# Generated by FakeRAM 2.0
VERSION 5.7 ;
BUSBITCHARS "[]" ;
PROPERTYDEFINITIONS
  MACRO width INTEGER ;
  MACRO depth INTEGER ;
  MACRO banks INTEGER ;
END PROPERTYDEFINITIONS
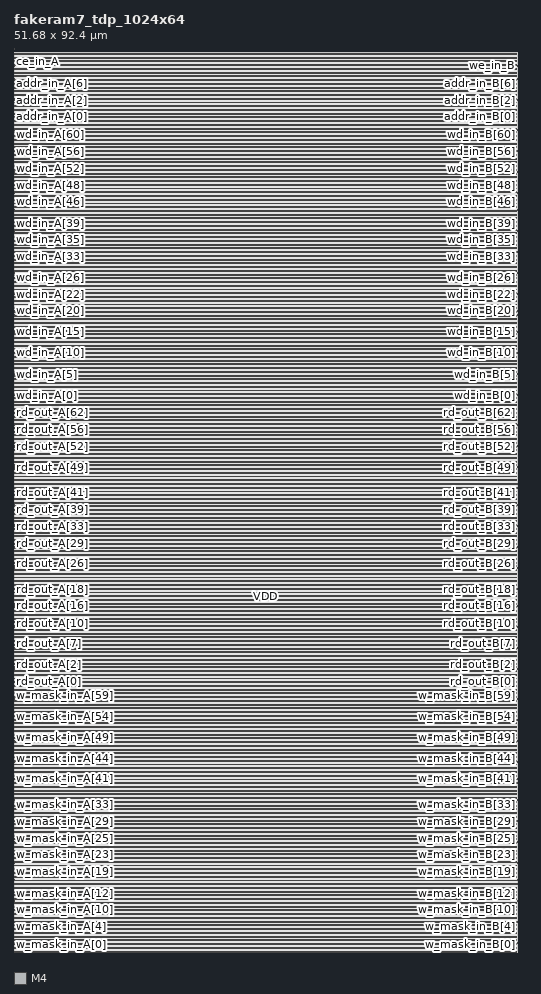
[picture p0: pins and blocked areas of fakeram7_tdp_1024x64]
MACRO fakeram7_tdp_1024x64
  PROPERTY width 64 ;
  PROPERTY depth 1024 ;
  PROPERTY banks 4 ;
  FOREIGN fakeram7_tdp_1024x64 0 0 ;
  SYMMETRY X Y ;
  SIZE 51.680 BY 92.400 ;
  CLASS BLOCK ;
  PIN w_mask_in_A[0]
    DIRECTION INPUT ;
    USE SIGNAL ;
    SHAPE ABUTMENT ;
    PORT
      LAYER M4 ;
      RECT 0.000 0.048 0.024 0.072 ;
    END
  END w_mask_in_A[0]
  PIN w_mask_in_B[0]
    DIRECTION INPUT ;
    USE SIGNAL ;
    SHAPE ABUTMENT ;
    PORT
      LAYER M4 ;
      RECT 51.656 0.048 51.680 0.072 ;
    END
  END w_mask_in_B[0]
  PIN w_mask_in_A[1]
    DIRECTION INPUT ;
    USE SIGNAL ;
    SHAPE ABUTMENT ;
    PORT
      LAYER M4 ;
      RECT 0.000 0.480 0.024 0.504 ;
    END
  END w_mask_in_A[1]
  PIN w_mask_in_B[1]
    DIRECTION INPUT ;
    USE SIGNAL ;
    SHAPE ABUTMENT ;
    PORT
      LAYER M4 ;
      RECT 51.656 0.480 51.680 0.504 ;
    END
  END w_mask_in_B[1]
  PIN w_mask_in_A[2]
    DIRECTION INPUT ;
    USE SIGNAL ;
    SHAPE ABUTMENT ;
    PORT
      LAYER M4 ;
      RECT 0.000 0.912 0.024 0.936 ;
    END
  END w_mask_in_A[2]
  PIN w_mask_in_B[2]
    DIRECTION INPUT ;
    USE SIGNAL ;
    SHAPE ABUTMENT ;
    PORT
      LAYER M4 ;
      RECT 51.656 0.912 51.680 0.936 ;
    END
  END w_mask_in_B[2]
  PIN w_mask_in_A[3]
    DIRECTION INPUT ;
    USE SIGNAL ;
    SHAPE ABUTMENT ;
    PORT
      LAYER M4 ;
      RECT 0.000 1.344 0.024 1.368 ;
    END
  END w_mask_in_A[3]
  PIN w_mask_in_B[3]
    DIRECTION INPUT ;
    USE SIGNAL ;
    SHAPE ABUTMENT ;
    PORT
      LAYER M4 ;
      RECT 51.656 1.344 51.680 1.368 ;
    END
  END w_mask_in_B[3]
  PIN w_mask_in_A[4]
    DIRECTION INPUT ;
    USE SIGNAL ;
    SHAPE ABUTMENT ;
    PORT
      LAYER M4 ;
      RECT 0.000 1.776 0.024 1.800 ;
    END
  END w_mask_in_A[4]
  PIN w_mask_in_B[4]
    DIRECTION INPUT ;
    USE SIGNAL ;
    SHAPE ABUTMENT ;
    PORT
      LAYER M4 ;
      RECT 51.656 1.776 51.680 1.800 ;
    END
  END w_mask_in_B[4]
  PIN w_mask_in_A[5]
    DIRECTION INPUT ;
    USE SIGNAL ;
    SHAPE ABUTMENT ;
    PORT
      LAYER M4 ;
      RECT 0.000 2.208 0.024 2.232 ;
    END
  END w_mask_in_A[5]
  PIN w_mask_in_B[5]
    DIRECTION INPUT ;
    USE SIGNAL ;
    SHAPE ABUTMENT ;
    PORT
      LAYER M4 ;
      RECT 51.656 2.208 51.680 2.232 ;
    END
  END w_mask_in_B[5]
  PIN w_mask_in_A[6]
    DIRECTION INPUT ;
    USE SIGNAL ;
    SHAPE ABUTMENT ;
    PORT
      LAYER M4 ;
      RECT 0.000 2.640 0.024 2.664 ;
    END
  END w_mask_in_A[6]
  PIN w_mask_in_B[6]
    DIRECTION INPUT ;
    USE SIGNAL ;
    SHAPE ABUTMENT ;
    PORT
      LAYER M4 ;
      RECT 51.656 2.640 51.680 2.664 ;
    END
  END w_mask_in_B[6]
  PIN w_mask_in_A[7]
    DIRECTION INPUT ;
    USE SIGNAL ;
    SHAPE ABUTMENT ;
    PORT
      LAYER M4 ;
      RECT 0.000 3.072 0.024 3.096 ;
    END
  END w_mask_in_A[7]
  PIN w_mask_in_B[7]
    DIRECTION INPUT ;
    USE SIGNAL ;
    SHAPE ABUTMENT ;
    PORT
      LAYER M4 ;
      RECT 51.656 3.072 51.680 3.096 ;
    END
  END w_mask_in_B[7]
  PIN w_mask_in_A[8]
    DIRECTION INPUT ;
    USE SIGNAL ;
    SHAPE ABUTMENT ;
    PORT
      LAYER M4 ;
      RECT 0.000 3.504 0.024 3.528 ;
    END
  END w_mask_in_A[8]
  PIN w_mask_in_B[8]
    DIRECTION INPUT ;
    USE SIGNAL ;
    SHAPE ABUTMENT ;
    PORT
      LAYER M4 ;
      RECT 51.656 3.504 51.680 3.528 ;
    END
  END w_mask_in_B[8]
  PIN w_mask_in_A[9]
    DIRECTION INPUT ;
    USE SIGNAL ;
    SHAPE ABUTMENT ;
    PORT
      LAYER M4 ;
      RECT 0.000 3.936 0.024 3.960 ;
    END
  END w_mask_in_A[9]
  PIN w_mask_in_B[9]
    DIRECTION INPUT ;
    USE SIGNAL ;
    SHAPE ABUTMENT ;
    PORT
      LAYER M4 ;
      RECT 51.656 3.936 51.680 3.960 ;
    END
  END w_mask_in_B[9]
  PIN w_mask_in_A[10]
    DIRECTION INPUT ;
    USE SIGNAL ;
    SHAPE ABUTMENT ;
    PORT
      LAYER M4 ;
      RECT 0.000 4.368 0.024 4.392 ;
    END
  END w_mask_in_A[10]
  PIN w_mask_in_B[10]
    DIRECTION INPUT ;
    USE SIGNAL ;
    SHAPE ABUTMENT ;
    PORT
      LAYER M4 ;
      RECT 51.656 4.368 51.680 4.392 ;
    END
  END w_mask_in_B[10]
  PIN w_mask_in_A[11]
    DIRECTION INPUT ;
    USE SIGNAL ;
    SHAPE ABUTMENT ;
    PORT
      LAYER M4 ;
      RECT 0.000 4.800 0.024 4.824 ;
    END
  END w_mask_in_A[11]
  PIN w_mask_in_B[11]
    DIRECTION INPUT ;
    USE SIGNAL ;
    SHAPE ABUTMENT ;
    PORT
      LAYER M4 ;
      RECT 51.656 4.800 51.680 4.824 ;
    END
  END w_mask_in_B[11]
  PIN w_mask_in_A[12]
    DIRECTION INPUT ;
    USE SIGNAL ;
    SHAPE ABUTMENT ;
    PORT
      LAYER M4 ;
      RECT 0.000 5.232 0.024 5.256 ;
    END
  END w_mask_in_A[12]
  PIN w_mask_in_B[12]
    DIRECTION INPUT ;
    USE SIGNAL ;
    SHAPE ABUTMENT ;
    PORT
      LAYER M4 ;
      RECT 51.656 5.232 51.680 5.256 ;
    END
  END w_mask_in_B[12]
  PIN w_mask_in_A[13]
    DIRECTION INPUT ;
    USE SIGNAL ;
    SHAPE ABUTMENT ;
    PORT
      LAYER M4 ;
      RECT 0.000 5.664 0.024 5.688 ;
    END
  END w_mask_in_A[13]
  PIN w_mask_in_B[13]
    DIRECTION INPUT ;
    USE SIGNAL ;
    SHAPE ABUTMENT ;
    PORT
      LAYER M4 ;
      RECT 51.656 5.664 51.680 5.688 ;
    END
  END w_mask_in_B[13]
  PIN w_mask_in_A[14]
    DIRECTION INPUT ;
    USE SIGNAL ;
    SHAPE ABUTMENT ;
    PORT
      LAYER M4 ;
      RECT 0.000 6.096 0.024 6.120 ;
    END
  END w_mask_in_A[14]
  PIN w_mask_in_B[14]
    DIRECTION INPUT ;
    USE SIGNAL ;
    SHAPE ABUTMENT ;
    PORT
      LAYER M4 ;
      RECT 51.656 6.096 51.680 6.120 ;
    END
  END w_mask_in_B[14]
  PIN w_mask_in_A[15]
    DIRECTION INPUT ;
    USE SIGNAL ;
    SHAPE ABUTMENT ;
    PORT
      LAYER M4 ;
      RECT 0.000 6.528 0.024 6.552 ;
    END
  END w_mask_in_A[15]
  PIN w_mask_in_B[15]
    DIRECTION INPUT ;
    USE SIGNAL ;
    SHAPE ABUTMENT ;
    PORT
      LAYER M4 ;
      RECT 51.656 6.528 51.680 6.552 ;
    END
  END w_mask_in_B[15]
  PIN w_mask_in_A[16]
    DIRECTION INPUT ;
    USE SIGNAL ;
    SHAPE ABUTMENT ;
    PORT
      LAYER M4 ;
      RECT 0.000 6.960 0.024 6.984 ;
    END
  END w_mask_in_A[16]
  PIN w_mask_in_B[16]
    DIRECTION INPUT ;
    USE SIGNAL ;
    SHAPE ABUTMENT ;
    PORT
      LAYER M4 ;
      RECT 51.656 6.960 51.680 6.984 ;
    END
  END w_mask_in_B[16]
  PIN w_mask_in_A[17]
    DIRECTION INPUT ;
    USE SIGNAL ;
    SHAPE ABUTMENT ;
    PORT
      LAYER M4 ;
      RECT 0.000 7.392 0.024 7.416 ;
    END
  END w_mask_in_A[17]
  PIN w_mask_in_B[17]
    DIRECTION INPUT ;
    USE SIGNAL ;
    SHAPE ABUTMENT ;
    PORT
      LAYER M4 ;
      RECT 51.656 7.392 51.680 7.416 ;
    END
  END w_mask_in_B[17]
  PIN w_mask_in_A[18]
    DIRECTION INPUT ;
    USE SIGNAL ;
    SHAPE ABUTMENT ;
    PORT
      LAYER M4 ;
      RECT 0.000 7.824 0.024 7.848 ;
    END
  END w_mask_in_A[18]
  PIN w_mask_in_B[18]
    DIRECTION INPUT ;
    USE SIGNAL ;
    SHAPE ABUTMENT ;
    PORT
      LAYER M4 ;
      RECT 51.656 7.824 51.680 7.848 ;
    END
  END w_mask_in_B[18]
  PIN w_mask_in_A[19]
    DIRECTION INPUT ;
    USE SIGNAL ;
    SHAPE ABUTMENT ;
    PORT
      LAYER M4 ;
      RECT 0.000 8.256 0.024 8.280 ;
    END
  END w_mask_in_A[19]
  PIN w_mask_in_B[19]
    DIRECTION INPUT ;
    USE SIGNAL ;
    SHAPE ABUTMENT ;
    PORT
      LAYER M4 ;
      RECT 51.656 8.256 51.680 8.280 ;
    END
  END w_mask_in_B[19]
  PIN w_mask_in_A[20]
    DIRECTION INPUT ;
    USE SIGNAL ;
    SHAPE ABUTMENT ;
    PORT
      LAYER M4 ;
      RECT 0.000 8.688 0.024 8.712 ;
    END
  END w_mask_in_A[20]
  PIN w_mask_in_B[20]
    DIRECTION INPUT ;
    USE SIGNAL ;
    SHAPE ABUTMENT ;
    PORT
      LAYER M4 ;
      RECT 51.656 8.688 51.680 8.712 ;
    END
  END w_mask_in_B[20]
  PIN w_mask_in_A[21]
    DIRECTION INPUT ;
    USE SIGNAL ;
    SHAPE ABUTMENT ;
    PORT
      LAYER M4 ;
      RECT 0.000 9.120 0.024 9.144 ;
    END
  END w_mask_in_A[21]
  PIN w_mask_in_B[21]
    DIRECTION INPUT ;
    USE SIGNAL ;
    SHAPE ABUTMENT ;
    PORT
      LAYER M4 ;
      RECT 51.656 9.120 51.680 9.144 ;
    END
  END w_mask_in_B[21]
  PIN w_mask_in_A[22]
    DIRECTION INPUT ;
    USE SIGNAL ;
    SHAPE ABUTMENT ;
    PORT
      LAYER M4 ;
      RECT 0.000 9.552 0.024 9.576 ;
    END
  END w_mask_in_A[22]
  PIN w_mask_in_B[22]
    DIRECTION INPUT ;
    USE SIGNAL ;
    SHAPE ABUTMENT ;
    PORT
      LAYER M4 ;
      RECT 51.656 9.552 51.680 9.576 ;
    END
  END w_mask_in_B[22]
  PIN w_mask_in_A[23]
    DIRECTION INPUT ;
    USE SIGNAL ;
    SHAPE ABUTMENT ;
    PORT
      LAYER M4 ;
      RECT 0.000 9.984 0.024 10.008 ;
    END
  END w_mask_in_A[23]
  PIN w_mask_in_B[23]
    DIRECTION INPUT ;
    USE SIGNAL ;
    SHAPE ABUTMENT ;
    PORT
      LAYER M4 ;
      RECT 51.656 9.984 51.680 10.008 ;
    END
  END w_mask_in_B[23]
  PIN w_mask_in_A[24]
    DIRECTION INPUT ;
    USE SIGNAL ;
    SHAPE ABUTMENT ;
    PORT
      LAYER M4 ;
      RECT 0.000 10.416 0.024 10.440 ;
    END
  END w_mask_in_A[24]
  PIN w_mask_in_B[24]
    DIRECTION INPUT ;
    USE SIGNAL ;
    SHAPE ABUTMENT ;
    PORT
      LAYER M4 ;
      RECT 51.656 10.416 51.680 10.440 ;
    END
  END w_mask_in_B[24]
  PIN w_mask_in_A[25]
    DIRECTION INPUT ;
    USE SIGNAL ;
    SHAPE ABUTMENT ;
    PORT
      LAYER M4 ;
      RECT 0.000 10.848 0.024 10.872 ;
    END
  END w_mask_in_A[25]
  PIN w_mask_in_B[25]
    DIRECTION INPUT ;
    USE SIGNAL ;
    SHAPE ABUTMENT ;
    PORT
      LAYER M4 ;
      RECT 51.656 10.848 51.680 10.872 ;
    END
  END w_mask_in_B[25]
  PIN w_mask_in_A[26]
    DIRECTION INPUT ;
    USE SIGNAL ;
    SHAPE ABUTMENT ;
    PORT
      LAYER M4 ;
      RECT 0.000 11.280 0.024 11.304 ;
    END
  END w_mask_in_A[26]
  PIN w_mask_in_B[26]
    DIRECTION INPUT ;
    USE SIGNAL ;
    SHAPE ABUTMENT ;
    PORT
      LAYER M4 ;
      RECT 51.656 11.280 51.680 11.304 ;
    END
  END w_mask_in_B[26]
  PIN w_mask_in_A[27]
    DIRECTION INPUT ;
    USE SIGNAL ;
    SHAPE ABUTMENT ;
    PORT
      LAYER M4 ;
      RECT 0.000 11.712 0.024 11.736 ;
    END
  END w_mask_in_A[27]
  PIN w_mask_in_B[27]
    DIRECTION INPUT ;
    USE SIGNAL ;
    SHAPE ABUTMENT ;
    PORT
      LAYER M4 ;
      RECT 51.656 11.712 51.680 11.736 ;
    END
  END w_mask_in_B[27]
  PIN w_mask_in_A[28]
    DIRECTION INPUT ;
    USE SIGNAL ;
    SHAPE ABUTMENT ;
    PORT
      LAYER M4 ;
      RECT 0.000 12.144 0.024 12.168 ;
    END
  END w_mask_in_A[28]
  PIN w_mask_in_B[28]
    DIRECTION INPUT ;
    USE SIGNAL ;
    SHAPE ABUTMENT ;
    PORT
      LAYER M4 ;
      RECT 51.656 12.144 51.680 12.168 ;
    END
  END w_mask_in_B[28]
  PIN w_mask_in_A[29]
    DIRECTION INPUT ;
    USE SIGNAL ;
    SHAPE ABUTMENT ;
    PORT
      LAYER M4 ;
      RECT 0.000 12.576 0.024 12.600 ;
    END
  END w_mask_in_A[29]
  PIN w_mask_in_B[29]
    DIRECTION INPUT ;
    USE SIGNAL ;
    SHAPE ABUTMENT ;
    PORT
      LAYER M4 ;
      RECT 51.656 12.576 51.680 12.600 ;
    END
  END w_mask_in_B[29]
  PIN w_mask_in_A[30]
    DIRECTION INPUT ;
    USE SIGNAL ;
    SHAPE ABUTMENT ;
    PORT
      LAYER M4 ;
      RECT 0.000 13.008 0.024 13.032 ;
    END
  END w_mask_in_A[30]
  PIN w_mask_in_B[30]
    DIRECTION INPUT ;
    USE SIGNAL ;
    SHAPE ABUTMENT ;
    PORT
      LAYER M4 ;
      RECT 51.656 13.008 51.680 13.032 ;
    END
  END w_mask_in_B[30]
  PIN w_mask_in_A[31]
    DIRECTION INPUT ;
    USE SIGNAL ;
    SHAPE ABUTMENT ;
    PORT
      LAYER M4 ;
      RECT 0.000 13.440 0.024 13.464 ;
    END
  END w_mask_in_A[31]
  PIN w_mask_in_B[31]
    DIRECTION INPUT ;
    USE SIGNAL ;
    SHAPE ABUTMENT ;
    PORT
      LAYER M4 ;
      RECT 51.656 13.440 51.680 13.464 ;
    END
  END w_mask_in_B[31]
  PIN w_mask_in_A[32]
    DIRECTION INPUT ;
    USE SIGNAL ;
    SHAPE ABUTMENT ;
    PORT
      LAYER M4 ;
      RECT 0.000 13.872 0.024 13.896 ;
    END
  END w_mask_in_A[32]
  PIN w_mask_in_B[32]
    DIRECTION INPUT ;
    USE SIGNAL ;
    SHAPE ABUTMENT ;
    PORT
      LAYER M4 ;
      RECT 51.656 13.872 51.680 13.896 ;
    END
  END w_mask_in_B[32]
  PIN w_mask_in_A[33]
    DIRECTION INPUT ;
    USE SIGNAL ;
    SHAPE ABUTMENT ;
    PORT
      LAYER M4 ;
      RECT 0.000 14.304 0.024 14.328 ;
    END
  END w_mask_in_A[33]
  PIN w_mask_in_B[33]
    DIRECTION INPUT ;
    USE SIGNAL ;
    SHAPE ABUTMENT ;
    PORT
      LAYER M4 ;
      RECT 51.656 14.304 51.680 14.328 ;
    END
  END w_mask_in_B[33]
  PIN w_mask_in_A[34]
    DIRECTION INPUT ;
    USE SIGNAL ;
    SHAPE ABUTMENT ;
    PORT
      LAYER M4 ;
      RECT 0.000 14.736 0.024 14.760 ;
    END
  END w_mask_in_A[34]
  PIN w_mask_in_B[34]
    DIRECTION INPUT ;
    USE SIGNAL ;
    SHAPE ABUTMENT ;
    PORT
      LAYER M4 ;
      RECT 51.656 14.736 51.680 14.760 ;
    END
  END w_mask_in_B[34]
  PIN w_mask_in_A[35]
    DIRECTION INPUT ;
    USE SIGNAL ;
    SHAPE ABUTMENT ;
    PORT
      LAYER M4 ;
      RECT 0.000 15.168 0.024 15.192 ;
    END
  END w_mask_in_A[35]
  PIN w_mask_in_B[35]
    DIRECTION INPUT ;
    USE SIGNAL ;
    SHAPE ABUTMENT ;
    PORT
      LAYER M4 ;
      RECT 51.656 15.168 51.680 15.192 ;
    END
  END w_mask_in_B[35]
  PIN w_mask_in_A[36]
    DIRECTION INPUT ;
    USE SIGNAL ;
    SHAPE ABUTMENT ;
    PORT
      LAYER M4 ;
      RECT 0.000 15.600 0.024 15.624 ;
    END
  END w_mask_in_A[36]
  PIN w_mask_in_B[36]
    DIRECTION INPUT ;
    USE SIGNAL ;
    SHAPE ABUTMENT ;
    PORT
      LAYER M4 ;
      RECT 51.656 15.600 51.680 15.624 ;
    END
  END w_mask_in_B[36]
  PIN w_mask_in_A[37]
    DIRECTION INPUT ;
    USE SIGNAL ;
    SHAPE ABUTMENT ;
    PORT
      LAYER M4 ;
      RECT 0.000 16.032 0.024 16.056 ;
    END
  END w_mask_in_A[37]
  PIN w_mask_in_B[37]
    DIRECTION INPUT ;
    USE SIGNAL ;
    SHAPE ABUTMENT ;
    PORT
      LAYER M4 ;
      RECT 51.656 16.032 51.680 16.056 ;
    END
  END w_mask_in_B[37]
  PIN w_mask_in_A[38]
    DIRECTION INPUT ;
    USE SIGNAL ;
    SHAPE ABUTMENT ;
    PORT
      LAYER M4 ;
      RECT 0.000 16.464 0.024 16.488 ;
    END
  END w_mask_in_A[38]
  PIN w_mask_in_B[38]
    DIRECTION INPUT ;
    USE SIGNAL ;
    SHAPE ABUTMENT ;
    PORT
      LAYER M4 ;
      RECT 51.656 16.464 51.680 16.488 ;
    END
  END w_mask_in_B[38]
  PIN w_mask_in_A[39]
    DIRECTION INPUT ;
    USE SIGNAL ;
    SHAPE ABUTMENT ;
    PORT
      LAYER M4 ;
      RECT 0.000 16.896 0.024 16.920 ;
    END
  END w_mask_in_A[39]
  PIN w_mask_in_B[39]
    DIRECTION INPUT ;
    USE SIGNAL ;
    SHAPE ABUTMENT ;
    PORT
      LAYER M4 ;
      RECT 51.656 16.896 51.680 16.920 ;
    END
  END w_mask_in_B[39]
  PIN w_mask_in_A[40]
    DIRECTION INPUT ;
    USE SIGNAL ;
    SHAPE ABUTMENT ;
    PORT
      LAYER M4 ;
      RECT 0.000 17.328 0.024 17.352 ;
    END
  END w_mask_in_A[40]
  PIN w_mask_in_B[40]
    DIRECTION INPUT ;
    USE SIGNAL ;
    SHAPE ABUTMENT ;
    PORT
      LAYER M4 ;
      RECT 51.656 17.328 51.680 17.352 ;
    END
  END w_mask_in_B[40]
  PIN w_mask_in_A[41]
    DIRECTION INPUT ;
    USE SIGNAL ;
    SHAPE ABUTMENT ;
    PORT
      LAYER M4 ;
      RECT 0.000 17.760 0.024 17.784 ;
    END
  END w_mask_in_A[41]
  PIN w_mask_in_B[41]
    DIRECTION INPUT ;
    USE SIGNAL ;
    SHAPE ABUTMENT ;
    PORT
      LAYER M4 ;
      RECT 51.656 17.760 51.680 17.784 ;
    END
  END w_mask_in_B[41]
  PIN w_mask_in_A[42]
    DIRECTION INPUT ;
    USE SIGNAL ;
    SHAPE ABUTMENT ;
    PORT
      LAYER M4 ;
      RECT 0.000 18.192 0.024 18.216 ;
    END
  END w_mask_in_A[42]
  PIN w_mask_in_B[42]
    DIRECTION INPUT ;
    USE SIGNAL ;
    SHAPE ABUTMENT ;
    PORT
      LAYER M4 ;
      RECT 51.656 18.192 51.680 18.216 ;
    END
  END w_mask_in_B[42]
  PIN w_mask_in_A[43]
    DIRECTION INPUT ;
    USE SIGNAL ;
    SHAPE ABUTMENT ;
    PORT
      LAYER M4 ;
      RECT 0.000 18.624 0.024 18.648 ;
    END
  END w_mask_in_A[43]
  PIN w_mask_in_B[43]
    DIRECTION INPUT ;
    USE SIGNAL ;
    SHAPE ABUTMENT ;
    PORT
      LAYER M4 ;
      RECT 51.656 18.624 51.680 18.648 ;
    END
  END w_mask_in_B[43]
  PIN w_mask_in_A[44]
    DIRECTION INPUT ;
    USE SIGNAL ;
    SHAPE ABUTMENT ;
    PORT
      LAYER M4 ;
      RECT 0.000 19.056 0.024 19.080 ;
    END
  END w_mask_in_A[44]
  PIN w_mask_in_B[44]
    DIRECTION INPUT ;
    USE SIGNAL ;
    SHAPE ABUTMENT ;
    PORT
      LAYER M4 ;
      RECT 51.656 19.056 51.680 19.080 ;
    END
  END w_mask_in_B[44]
  PIN w_mask_in_A[45]
    DIRECTION INPUT ;
    USE SIGNAL ;
    SHAPE ABUTMENT ;
    PORT
      LAYER M4 ;
      RECT 0.000 19.488 0.024 19.512 ;
    END
  END w_mask_in_A[45]
  PIN w_mask_in_B[45]
    DIRECTION INPUT ;
    USE SIGNAL ;
    SHAPE ABUTMENT ;
    PORT
      LAYER M4 ;
      RECT 51.656 19.488 51.680 19.512 ;
    END
  END w_mask_in_B[45]
  PIN w_mask_in_A[46]
    DIRECTION INPUT ;
    USE SIGNAL ;
    SHAPE ABUTMENT ;
    PORT
      LAYER M4 ;
      RECT 0.000 19.920 0.024 19.944 ;
    END
  END w_mask_in_A[46]
  PIN w_mask_in_B[46]
    DIRECTION INPUT ;
    USE SIGNAL ;
    SHAPE ABUTMENT ;
    PORT
      LAYER M4 ;
      RECT 51.656 19.920 51.680 19.944 ;
    END
  END w_mask_in_B[46]
  PIN w_mask_in_A[47]
    DIRECTION INPUT ;
    USE SIGNAL ;
    SHAPE ABUTMENT ;
    PORT
      LAYER M4 ;
      RECT 0.000 20.352 0.024 20.376 ;
    END
  END w_mask_in_A[47]
  PIN w_mask_in_B[47]
    DIRECTION INPUT ;
    USE SIGNAL ;
    SHAPE ABUTMENT ;
    PORT
      LAYER M4 ;
      RECT 51.656 20.352 51.680 20.376 ;
    END
  END w_mask_in_B[47]
  PIN w_mask_in_A[48]
    DIRECTION INPUT ;
    USE SIGNAL ;
    SHAPE ABUTMENT ;
    PORT
      LAYER M4 ;
      RECT 0.000 20.784 0.024 20.808 ;
    END
  END w_mask_in_A[48]
  PIN w_mask_in_B[48]
    DIRECTION INPUT ;
    USE SIGNAL ;
    SHAPE ABUTMENT ;
    PORT
      LAYER M4 ;
      RECT 51.656 20.784 51.680 20.808 ;
    END
  END w_mask_in_B[48]
  PIN w_mask_in_A[49]
    DIRECTION INPUT ;
    USE SIGNAL ;
    SHAPE ABUTMENT ;
    PORT
      LAYER M4 ;
      RECT 0.000 21.216 0.024 21.240 ;
    END
  END w_mask_in_A[49]
  PIN w_mask_in_B[49]
    DIRECTION INPUT ;
    USE SIGNAL ;
    SHAPE ABUTMENT ;
    PORT
      LAYER M4 ;
      RECT 51.656 21.216 51.680 21.240 ;
    END
  END w_mask_in_B[49]
  PIN w_mask_in_A[50]
    DIRECTION INPUT ;
    USE SIGNAL ;
    SHAPE ABUTMENT ;
    PORT
      LAYER M4 ;
      RECT 0.000 21.648 0.024 21.672 ;
    END
  END w_mask_in_A[50]
  PIN w_mask_in_B[50]
    DIRECTION INPUT ;
    USE SIGNAL ;
    SHAPE ABUTMENT ;
    PORT
      LAYER M4 ;
      RECT 51.656 21.648 51.680 21.672 ;
    END
  END w_mask_in_B[50]
  PIN w_mask_in_A[51]
    DIRECTION INPUT ;
    USE SIGNAL ;
    SHAPE ABUTMENT ;
    PORT
      LAYER M4 ;
      RECT 0.000 22.080 0.024 22.104 ;
    END
  END w_mask_in_A[51]
  PIN w_mask_in_B[51]
    DIRECTION INPUT ;
    USE SIGNAL ;
    SHAPE ABUTMENT ;
    PORT
      LAYER M4 ;
      RECT 51.656 22.080 51.680 22.104 ;
    END
  END w_mask_in_B[51]
  PIN w_mask_in_A[52]
    DIRECTION INPUT ;
    USE SIGNAL ;
    SHAPE ABUTMENT ;
    PORT
      LAYER M4 ;
      RECT 0.000 22.512 0.024 22.536 ;
    END
  END w_mask_in_A[52]
  PIN w_mask_in_B[52]
    DIRECTION INPUT ;
    USE SIGNAL ;
    SHAPE ABUTMENT ;
    PORT
      LAYER M4 ;
      RECT 51.656 22.512 51.680 22.536 ;
    END
  END w_mask_in_B[52]
  PIN w_mask_in_A[53]
    DIRECTION INPUT ;
    USE SIGNAL ;
    SHAPE ABUTMENT ;
    PORT
      LAYER M4 ;
      RECT 0.000 22.944 0.024 22.968 ;
    END
  END w_mask_in_A[53]
  PIN w_mask_in_B[53]
    DIRECTION INPUT ;
    USE SIGNAL ;
    SHAPE ABUTMENT ;
    PORT
      LAYER M4 ;
      RECT 51.656 22.944 51.680 22.968 ;
    END
  END w_mask_in_B[53]
  PIN w_mask_in_A[54]
    DIRECTION INPUT ;
    USE SIGNAL ;
    SHAPE ABUTMENT ;
    PORT
      LAYER M4 ;
      RECT 0.000 23.376 0.024 23.400 ;
    END
  END w_mask_in_A[54]
  PIN w_mask_in_B[54]
    DIRECTION INPUT ;
    USE SIGNAL ;
    SHAPE ABUTMENT ;
    PORT
      LAYER M4 ;
      RECT 51.656 23.376 51.680 23.400 ;
    END
  END w_mask_in_B[54]
  PIN w_mask_in_A[55]
    DIRECTION INPUT ;
    USE SIGNAL ;
    SHAPE ABUTMENT ;
    PORT
      LAYER M4 ;
      RECT 0.000 23.808 0.024 23.832 ;
    END
  END w_mask_in_A[55]
  PIN w_mask_in_B[55]
    DIRECTION INPUT ;
    USE SIGNAL ;
    SHAPE ABUTMENT ;
    PORT
      LAYER M4 ;
      RECT 51.656 23.808 51.680 23.832 ;
    END
  END w_mask_in_B[55]
  PIN w_mask_in_A[56]
    DIRECTION INPUT ;
    USE SIGNAL ;
    SHAPE ABUTMENT ;
    PORT
      LAYER M4 ;
      RECT 0.000 24.240 0.024 24.264 ;
    END
  END w_mask_in_A[56]
  PIN w_mask_in_B[56]
    DIRECTION INPUT ;
    USE SIGNAL ;
    SHAPE ABUTMENT ;
    PORT
      LAYER M4 ;
      RECT 51.656 24.240 51.680 24.264 ;
    END
  END w_mask_in_B[56]
  PIN w_mask_in_A[57]
    DIRECTION INPUT ;
    USE SIGNAL ;
    SHAPE ABUTMENT ;
    PORT
      LAYER M4 ;
      RECT 0.000 24.672 0.024 24.696 ;
    END
  END w_mask_in_A[57]
  PIN w_mask_in_B[57]
    DIRECTION INPUT ;
    USE SIGNAL ;
    SHAPE ABUTMENT ;
    PORT
      LAYER M4 ;
      RECT 51.656 24.672 51.680 24.696 ;
    END
  END w_mask_in_B[57]
  PIN w_mask_in_A[58]
    DIRECTION INPUT ;
    USE SIGNAL ;
    SHAPE ABUTMENT ;
    PORT
      LAYER M4 ;
      RECT 0.000 25.104 0.024 25.128 ;
    END
  END w_mask_in_A[58]
  PIN w_mask_in_B[58]
    DIRECTION INPUT ;
    USE SIGNAL ;
    SHAPE ABUTMENT ;
    PORT
      LAYER M4 ;
      RECT 51.656 25.104 51.680 25.128 ;
    END
  END w_mask_in_B[58]
  PIN w_mask_in_A[59]
    DIRECTION INPUT ;
    USE SIGNAL ;
    SHAPE ABUTMENT ;
    PORT
      LAYER M4 ;
      RECT 0.000 25.536 0.024 25.560 ;
    END
  END w_mask_in_A[59]
  PIN w_mask_in_B[59]
    DIRECTION INPUT ;
    USE SIGNAL ;
    SHAPE ABUTMENT ;
    PORT
      LAYER M4 ;
      RECT 51.656 25.536 51.680 25.560 ;
    END
  END w_mask_in_B[59]
  PIN w_mask_in_A[60]
    DIRECTION INPUT ;
    USE SIGNAL ;
    SHAPE ABUTMENT ;
    PORT
      LAYER M4 ;
      RECT 0.000 25.968 0.024 25.992 ;
    END
  END w_mask_in_A[60]
  PIN w_mask_in_B[60]
    DIRECTION INPUT ;
    USE SIGNAL ;
    SHAPE ABUTMENT ;
    PORT
      LAYER M4 ;
      RECT 51.656 25.968 51.680 25.992 ;
    END
  END w_mask_in_B[60]
  PIN w_mask_in_A[61]
    DIRECTION INPUT ;
    USE SIGNAL ;
    SHAPE ABUTMENT ;
    PORT
      LAYER M4 ;
      RECT 0.000 26.400 0.024 26.424 ;
    END
  END w_mask_in_A[61]
  PIN w_mask_in_B[61]
    DIRECTION INPUT ;
    USE SIGNAL ;
    SHAPE ABUTMENT ;
    PORT
      LAYER M4 ;
      RECT 51.656 26.400 51.680 26.424 ;
    END
  END w_mask_in_B[61]
  PIN w_mask_in_A[62]
    DIRECTION INPUT ;
    USE SIGNAL ;
    SHAPE ABUTMENT ;
    PORT
      LAYER M4 ;
      RECT 0.000 26.832 0.024 26.856 ;
    END
  END w_mask_in_A[62]
  PIN w_mask_in_B[62]
    DIRECTION INPUT ;
    USE SIGNAL ;
    SHAPE ABUTMENT ;
    PORT
      LAYER M4 ;
      RECT 51.656 26.832 51.680 26.856 ;
    END
  END w_mask_in_B[62]
  PIN w_mask_in_A[63]
    DIRECTION INPUT ;
    USE SIGNAL ;
    SHAPE ABUTMENT ;
    PORT
      LAYER M4 ;
      RECT 0.000 27.264 0.024 27.288 ;
    END
  END w_mask_in_A[63]
  PIN w_mask_in_B[63]
    DIRECTION INPUT ;
    USE SIGNAL ;
    SHAPE ABUTMENT ;
    PORT
      LAYER M4 ;
      RECT 51.656 27.264 51.680 27.288 ;
    END
  END w_mask_in_B[63]
  PIN rd_out_A[0]
    DIRECTION OUTPUT ;
    USE SIGNAL ;
    SHAPE ABUTMENT ;
    PORT
      LAYER M4 ;
      RECT 0.000 28.608 0.024 28.632 ;
    END
  END rd_out_A[0]
  PIN rd_out_B[0]
    DIRECTION OUTPUT ;
    USE SIGNAL ;
    SHAPE ABUTMENT ;
    PORT
      LAYER M4 ;
      RECT 51.656 28.608 51.680 28.632 ;
    END
  END rd_out_B[0]
  PIN rd_out_A[1]
    DIRECTION OUTPUT ;
    USE SIGNAL ;
    SHAPE ABUTMENT ;
    PORT
      LAYER M4 ;
      RECT 0.000 29.040 0.024 29.064 ;
    END
  END rd_out_A[1]
  PIN rd_out_B[1]
    DIRECTION OUTPUT ;
    USE SIGNAL ;
    SHAPE ABUTMENT ;
    PORT
      LAYER M4 ;
      RECT 51.656 29.040 51.680 29.064 ;
    END
  END rd_out_B[1]
  PIN rd_out_A[2]
    DIRECTION OUTPUT ;
    USE SIGNAL ;
    SHAPE ABUTMENT ;
    PORT
      LAYER M4 ;
      RECT 0.000 29.472 0.024 29.496 ;
    END
  END rd_out_A[2]
  PIN rd_out_B[2]
    DIRECTION OUTPUT ;
    USE SIGNAL ;
    SHAPE ABUTMENT ;
    PORT
      LAYER M4 ;
      RECT 51.656 29.472 51.680 29.496 ;
    END
  END rd_out_B[2]
  PIN rd_out_A[3]
    DIRECTION OUTPUT ;
    USE SIGNAL ;
    SHAPE ABUTMENT ;
    PORT
      LAYER M4 ;
      RECT 0.000 29.904 0.024 29.928 ;
    END
  END rd_out_A[3]
  PIN rd_out_B[3]
    DIRECTION OUTPUT ;
    USE SIGNAL ;
    SHAPE ABUTMENT ;
    PORT
      LAYER M4 ;
      RECT 51.656 29.904 51.680 29.928 ;
    END
  END rd_out_B[3]
  PIN rd_out_A[4]
    DIRECTION OUTPUT ;
    USE SIGNAL ;
    SHAPE ABUTMENT ;
    PORT
      LAYER M4 ;
      RECT 0.000 30.336 0.024 30.360 ;
    END
  END rd_out_A[4]
  PIN rd_out_B[4]
    DIRECTION OUTPUT ;
    USE SIGNAL ;
    SHAPE ABUTMENT ;
    PORT
      LAYER M4 ;
      RECT 51.656 30.336 51.680 30.360 ;
    END
  END rd_out_B[4]
  PIN rd_out_A[5]
    DIRECTION OUTPUT ;
    USE SIGNAL ;
    SHAPE ABUTMENT ;
    PORT
      LAYER M4 ;
      RECT 0.000 30.768 0.024 30.792 ;
    END
  END rd_out_A[5]
  PIN rd_out_B[5]
    DIRECTION OUTPUT ;
    USE SIGNAL ;
    SHAPE ABUTMENT ;
    PORT
      LAYER M4 ;
      RECT 51.656 30.768 51.680 30.792 ;
    END
  END rd_out_B[5]
  PIN rd_out_A[6]
    DIRECTION OUTPUT ;
    USE SIGNAL ;
    SHAPE ABUTMENT ;
    PORT
      LAYER M4 ;
      RECT 0.000 31.200 0.024 31.224 ;
    END
  END rd_out_A[6]
  PIN rd_out_B[6]
    DIRECTION OUTPUT ;
    USE SIGNAL ;
    SHAPE ABUTMENT ;
    PORT
      LAYER M4 ;
      RECT 51.656 31.200 51.680 31.224 ;
    END
  END rd_out_B[6]
  PIN rd_out_A[7]
    DIRECTION OUTPUT ;
    USE SIGNAL ;
    SHAPE ABUTMENT ;
    PORT
      LAYER M4 ;
      RECT 0.000 31.632 0.024 31.656 ;
    END
  END rd_out_A[7]
  PIN rd_out_B[7]
    DIRECTION OUTPUT ;
    USE SIGNAL ;
    SHAPE ABUTMENT ;
    PORT
      LAYER M4 ;
      RECT 51.656 31.632 51.680 31.656 ;
    END
  END rd_out_B[7]
  PIN rd_out_A[8]
    DIRECTION OUTPUT ;
    USE SIGNAL ;
    SHAPE ABUTMENT ;
    PORT
      LAYER M4 ;
      RECT 0.000 32.064 0.024 32.088 ;
    END
  END rd_out_A[8]
  PIN rd_out_B[8]
    DIRECTION OUTPUT ;
    USE SIGNAL ;
    SHAPE ABUTMENT ;
    PORT
      LAYER M4 ;
      RECT 51.656 32.064 51.680 32.088 ;
    END
  END rd_out_B[8]
  PIN rd_out_A[9]
    DIRECTION OUTPUT ;
    USE SIGNAL ;
    SHAPE ABUTMENT ;
    PORT
      LAYER M4 ;
      RECT 0.000 32.496 0.024 32.520 ;
    END
  END rd_out_A[9]
  PIN rd_out_B[9]
    DIRECTION OUTPUT ;
    USE SIGNAL ;
    SHAPE ABUTMENT ;
    PORT
      LAYER M4 ;
      RECT 51.656 32.496 51.680 32.520 ;
    END
  END rd_out_B[9]
  PIN rd_out_A[10]
    DIRECTION OUTPUT ;
    USE SIGNAL ;
    SHAPE ABUTMENT ;
    PORT
      LAYER M4 ;
      RECT 0.000 32.928 0.024 32.952 ;
    END
  END rd_out_A[10]
  PIN rd_out_B[10]
    DIRECTION OUTPUT ;
    USE SIGNAL ;
    SHAPE ABUTMENT ;
    PORT
      LAYER M4 ;
      RECT 51.656 32.928 51.680 32.952 ;
    END
  END rd_out_B[10]
  PIN rd_out_A[11]
    DIRECTION OUTPUT ;
    USE SIGNAL ;
    SHAPE ABUTMENT ;
    PORT
      LAYER M4 ;
      RECT 0.000 33.360 0.024 33.384 ;
    END
  END rd_out_A[11]
  PIN rd_out_B[11]
    DIRECTION OUTPUT ;
    USE SIGNAL ;
    SHAPE ABUTMENT ;
    PORT
      LAYER M4 ;
      RECT 51.656 33.360 51.680 33.384 ;
    END
  END rd_out_B[11]
  PIN rd_out_A[12]
    DIRECTION OUTPUT ;
    USE SIGNAL ;
    SHAPE ABUTMENT ;
    PORT
      LAYER M4 ;
      RECT 0.000 33.792 0.024 33.816 ;
    END
  END rd_out_A[12]
  PIN rd_out_B[12]
    DIRECTION OUTPUT ;
    USE SIGNAL ;
    SHAPE ABUTMENT ;
    PORT
      LAYER M4 ;
      RECT 51.656 33.792 51.680 33.816 ;
    END
  END rd_out_B[12]
  PIN rd_out_A[13]
    DIRECTION OUTPUT ;
    USE SIGNAL ;
    SHAPE ABUTMENT ;
    PORT
      LAYER M4 ;
      RECT 0.000 34.224 0.024 34.248 ;
    END
  END rd_out_A[13]
  PIN rd_out_B[13]
    DIRECTION OUTPUT ;
    USE SIGNAL ;
    SHAPE ABUTMENT ;
    PORT
      LAYER M4 ;
      RECT 51.656 34.224 51.680 34.248 ;
    END
  END rd_out_B[13]
  PIN rd_out_A[14]
    DIRECTION OUTPUT ;
    USE SIGNAL ;
    SHAPE ABUTMENT ;
    PORT
      LAYER M4 ;
      RECT 0.000 34.656 0.024 34.680 ;
    END
  END rd_out_A[14]
  PIN rd_out_B[14]
    DIRECTION OUTPUT ;
    USE SIGNAL ;
    SHAPE ABUTMENT ;
    PORT
      LAYER M4 ;
      RECT 51.656 34.656 51.680 34.680 ;
    END
  END rd_out_B[14]
  PIN rd_out_A[15]
    DIRECTION OUTPUT ;
    USE SIGNAL ;
    SHAPE ABUTMENT ;
    PORT
      LAYER M4 ;
      RECT 0.000 35.088 0.024 35.112 ;
    END
  END rd_out_A[15]
  PIN rd_out_B[15]
    DIRECTION OUTPUT ;
    USE SIGNAL ;
    SHAPE ABUTMENT ;
    PORT
      LAYER M4 ;
      RECT 51.656 35.088 51.680 35.112 ;
    END
  END rd_out_B[15]
  PIN rd_out_A[16]
    DIRECTION OUTPUT ;
    USE SIGNAL ;
    SHAPE ABUTMENT ;
    PORT
      LAYER M4 ;
      RECT 0.000 35.520 0.024 35.544 ;
    END
  END rd_out_A[16]
  PIN rd_out_B[16]
    DIRECTION OUTPUT ;
    USE SIGNAL ;
    SHAPE ABUTMENT ;
    PORT
      LAYER M4 ;
      RECT 51.656 35.520 51.680 35.544 ;
    END
  END rd_out_B[16]
  PIN rd_out_A[17]
    DIRECTION OUTPUT ;
    USE SIGNAL ;
    SHAPE ABUTMENT ;
    PORT
      LAYER M4 ;
      RECT 0.000 35.952 0.024 35.976 ;
    END
  END rd_out_A[17]
  PIN rd_out_B[17]
    DIRECTION OUTPUT ;
    USE SIGNAL ;
    SHAPE ABUTMENT ;
    PORT
      LAYER M4 ;
      RECT 51.656 35.952 51.680 35.976 ;
    END
  END rd_out_B[17]
  PIN rd_out_A[18]
    DIRECTION OUTPUT ;
    USE SIGNAL ;
    SHAPE ABUTMENT ;
    PORT
      LAYER M4 ;
      RECT 0.000 36.384 0.024 36.408 ;
    END
  END rd_out_A[18]
  PIN rd_out_B[18]
    DIRECTION OUTPUT ;
    USE SIGNAL ;
    SHAPE ABUTMENT ;
    PORT
      LAYER M4 ;
      RECT 51.656 36.384 51.680 36.408 ;
    END
  END rd_out_B[18]
  PIN rd_out_A[19]
    DIRECTION OUTPUT ;
    USE SIGNAL ;
    SHAPE ABUTMENT ;
    PORT
      LAYER M4 ;
      RECT 0.000 36.816 0.024 36.840 ;
    END
  END rd_out_A[19]
  PIN rd_out_B[19]
    DIRECTION OUTPUT ;
    USE SIGNAL ;
    SHAPE ABUTMENT ;
    PORT
      LAYER M4 ;
      RECT 51.656 36.816 51.680 36.840 ;
    END
  END rd_out_B[19]
  PIN rd_out_A[20]
    DIRECTION OUTPUT ;
    USE SIGNAL ;
    SHAPE ABUTMENT ;
    PORT
      LAYER M4 ;
      RECT 0.000 37.248 0.024 37.272 ;
    END
  END rd_out_A[20]
  PIN rd_out_B[20]
    DIRECTION OUTPUT ;
    USE SIGNAL ;
    SHAPE ABUTMENT ;
    PORT
      LAYER M4 ;
      RECT 51.656 37.248 51.680 37.272 ;
    END
  END rd_out_B[20]
  PIN rd_out_A[21]
    DIRECTION OUTPUT ;
    USE SIGNAL ;
    SHAPE ABUTMENT ;
    PORT
      LAYER M4 ;
      RECT 0.000 37.680 0.024 37.704 ;
    END
  END rd_out_A[21]
  PIN rd_out_B[21]
    DIRECTION OUTPUT ;
    USE SIGNAL ;
    SHAPE ABUTMENT ;
    PORT
      LAYER M4 ;
      RECT 51.656 37.680 51.680 37.704 ;
    END
  END rd_out_B[21]
  PIN rd_out_A[22]
    DIRECTION OUTPUT ;
    USE SIGNAL ;
    SHAPE ABUTMENT ;
    PORT
      LAYER M4 ;
      RECT 0.000 38.112 0.024 38.136 ;
    END
  END rd_out_A[22]
  PIN rd_out_B[22]
    DIRECTION OUTPUT ;
    USE SIGNAL ;
    SHAPE ABUTMENT ;
    PORT
      LAYER M4 ;
      RECT 51.656 38.112 51.680 38.136 ;
    END
  END rd_out_B[22]
  PIN rd_out_A[23]
    DIRECTION OUTPUT ;
    USE SIGNAL ;
    SHAPE ABUTMENT ;
    PORT
      LAYER M4 ;
      RECT 0.000 38.544 0.024 38.568 ;
    END
  END rd_out_A[23]
  PIN rd_out_B[23]
    DIRECTION OUTPUT ;
    USE SIGNAL ;
    SHAPE ABUTMENT ;
    PORT
      LAYER M4 ;
      RECT 51.656 38.544 51.680 38.568 ;
    END
  END rd_out_B[23]
  PIN rd_out_A[24]
    DIRECTION OUTPUT ;
    USE SIGNAL ;
    SHAPE ABUTMENT ;
    PORT
      LAYER M4 ;
      RECT 0.000 38.976 0.024 39.000 ;
    END
  END rd_out_A[24]
  PIN rd_out_B[24]
    DIRECTION OUTPUT ;
    USE SIGNAL ;
    SHAPE ABUTMENT ;
    PORT
      LAYER M4 ;
      RECT 51.656 38.976 51.680 39.000 ;
    END
  END rd_out_B[24]
  PIN rd_out_A[25]
    DIRECTION OUTPUT ;
    USE SIGNAL ;
    SHAPE ABUTMENT ;
    PORT
      LAYER M4 ;
      RECT 0.000 39.408 0.024 39.432 ;
    END
  END rd_out_A[25]
  PIN rd_out_B[25]
    DIRECTION OUTPUT ;
    USE SIGNAL ;
    SHAPE ABUTMENT ;
    PORT
      LAYER M4 ;
      RECT 51.656 39.408 51.680 39.432 ;
    END
  END rd_out_B[25]
  PIN rd_out_A[26]
    DIRECTION OUTPUT ;
    USE SIGNAL ;
    SHAPE ABUTMENT ;
    PORT
      LAYER M4 ;
      RECT 0.000 39.840 0.024 39.864 ;
    END
  END rd_out_A[26]
  PIN rd_out_B[26]
    DIRECTION OUTPUT ;
    USE SIGNAL ;
    SHAPE ABUTMENT ;
    PORT
      LAYER M4 ;
      RECT 51.656 39.840 51.680 39.864 ;
    END
  END rd_out_B[26]
  PIN rd_out_A[27]
    DIRECTION OUTPUT ;
    USE SIGNAL ;
    SHAPE ABUTMENT ;
    PORT
      LAYER M4 ;
      RECT 0.000 40.272 0.024 40.296 ;
    END
  END rd_out_A[27]
  PIN rd_out_B[27]
    DIRECTION OUTPUT ;
    USE SIGNAL ;
    SHAPE ABUTMENT ;
    PORT
      LAYER M4 ;
      RECT 51.656 40.272 51.680 40.296 ;
    END
  END rd_out_B[27]
  PIN rd_out_A[28]
    DIRECTION OUTPUT ;
    USE SIGNAL ;
    SHAPE ABUTMENT ;
    PORT
      LAYER M4 ;
      RECT 0.000 40.704 0.024 40.728 ;
    END
  END rd_out_A[28]
  PIN rd_out_B[28]
    DIRECTION OUTPUT ;
    USE SIGNAL ;
    SHAPE ABUTMENT ;
    PORT
      LAYER M4 ;
      RECT 51.656 40.704 51.680 40.728 ;
    END
  END rd_out_B[28]
  PIN rd_out_A[29]
    DIRECTION OUTPUT ;
    USE SIGNAL ;
    SHAPE ABUTMENT ;
    PORT
      LAYER M4 ;
      RECT 0.000 41.136 0.024 41.160 ;
    END
  END rd_out_A[29]
  PIN rd_out_B[29]
    DIRECTION OUTPUT ;
    USE SIGNAL ;
    SHAPE ABUTMENT ;
    PORT
      LAYER M4 ;
      RECT 51.656 41.136 51.680 41.160 ;
    END
  END rd_out_B[29]
  PIN rd_out_A[30]
    DIRECTION OUTPUT ;
    USE SIGNAL ;
    SHAPE ABUTMENT ;
    PORT
      LAYER M4 ;
      RECT 0.000 41.568 0.024 41.592 ;
    END
  END rd_out_A[30]
  PIN rd_out_B[30]
    DIRECTION OUTPUT ;
    USE SIGNAL ;
    SHAPE ABUTMENT ;
    PORT
      LAYER M4 ;
      RECT 51.656 41.568 51.680 41.592 ;
    END
  END rd_out_B[30]
  PIN rd_out_A[31]
    DIRECTION OUTPUT ;
    USE SIGNAL ;
    SHAPE ABUTMENT ;
    PORT
      LAYER M4 ;
      RECT 0.000 42.000 0.024 42.024 ;
    END
  END rd_out_A[31]
  PIN rd_out_B[31]
    DIRECTION OUTPUT ;
    USE SIGNAL ;
    SHAPE ABUTMENT ;
    PORT
      LAYER M4 ;
      RECT 51.656 42.000 51.680 42.024 ;
    END
  END rd_out_B[31]
  PIN rd_out_A[32]
    DIRECTION OUTPUT ;
    USE SIGNAL ;
    SHAPE ABUTMENT ;
    PORT
      LAYER M4 ;
      RECT 0.000 42.432 0.024 42.456 ;
    END
  END rd_out_A[32]
  PIN rd_out_B[32]
    DIRECTION OUTPUT ;
    USE SIGNAL ;
    SHAPE ABUTMENT ;
    PORT
      LAYER M4 ;
      RECT 51.656 42.432 51.680 42.456 ;
    END
  END rd_out_B[32]
  PIN rd_out_A[33]
    DIRECTION OUTPUT ;
    USE SIGNAL ;
    SHAPE ABUTMENT ;
    PORT
      LAYER M4 ;
      RECT 0.000 42.864 0.024 42.888 ;
    END
  END rd_out_A[33]
  PIN rd_out_B[33]
    DIRECTION OUTPUT ;
    USE SIGNAL ;
    SHAPE ABUTMENT ;
    PORT
      LAYER M4 ;
      RECT 51.656 42.864 51.680 42.888 ;
    END
  END rd_out_B[33]
  PIN rd_out_A[34]
    DIRECTION OUTPUT ;
    USE SIGNAL ;
    SHAPE ABUTMENT ;
    PORT
      LAYER M4 ;
      RECT 0.000 43.296 0.024 43.320 ;
    END
  END rd_out_A[34]
  PIN rd_out_B[34]
    DIRECTION OUTPUT ;
    USE SIGNAL ;
    SHAPE ABUTMENT ;
    PORT
      LAYER M4 ;
      RECT 51.656 43.296 51.680 43.320 ;
    END
  END rd_out_B[34]
  PIN rd_out_A[35]
    DIRECTION OUTPUT ;
    USE SIGNAL ;
    SHAPE ABUTMENT ;
    PORT
      LAYER M4 ;
      RECT 0.000 43.728 0.024 43.752 ;
    END
  END rd_out_A[35]
  PIN rd_out_B[35]
    DIRECTION OUTPUT ;
    USE SIGNAL ;
    SHAPE ABUTMENT ;
    PORT
      LAYER M4 ;
      RECT 51.656 43.728 51.680 43.752 ;
    END
  END rd_out_B[35]
  PIN rd_out_A[36]
    DIRECTION OUTPUT ;
    USE SIGNAL ;
    SHAPE ABUTMENT ;
    PORT
      LAYER M4 ;
      RECT 0.000 44.160 0.024 44.184 ;
    END
  END rd_out_A[36]
  PIN rd_out_B[36]
    DIRECTION OUTPUT ;
    USE SIGNAL ;
    SHAPE ABUTMENT ;
    PORT
      LAYER M4 ;
      RECT 51.656 44.160 51.680 44.184 ;
    END
  END rd_out_B[36]
  PIN rd_out_A[37]
    DIRECTION OUTPUT ;
    USE SIGNAL ;
    SHAPE ABUTMENT ;
    PORT
      LAYER M4 ;
      RECT 0.000 44.592 0.024 44.616 ;
    END
  END rd_out_A[37]
  PIN rd_out_B[37]
    DIRECTION OUTPUT ;
    USE SIGNAL ;
    SHAPE ABUTMENT ;
    PORT
      LAYER M4 ;
      RECT 51.656 44.592 51.680 44.616 ;
    END
  END rd_out_B[37]
  PIN rd_out_A[38]
    DIRECTION OUTPUT ;
    USE SIGNAL ;
    SHAPE ABUTMENT ;
    PORT
      LAYER M4 ;
      RECT 0.000 45.024 0.024 45.048 ;
    END
  END rd_out_A[38]
  PIN rd_out_B[38]
    DIRECTION OUTPUT ;
    USE SIGNAL ;
    SHAPE ABUTMENT ;
    PORT
      LAYER M4 ;
      RECT 51.656 45.024 51.680 45.048 ;
    END
  END rd_out_B[38]
  PIN rd_out_A[39]
    DIRECTION OUTPUT ;
    USE SIGNAL ;
    SHAPE ABUTMENT ;
    PORT
      LAYER M4 ;
      RECT 0.000 45.456 0.024 45.480 ;
    END
  END rd_out_A[39]
  PIN rd_out_B[39]
    DIRECTION OUTPUT ;
    USE SIGNAL ;
    SHAPE ABUTMENT ;
    PORT
      LAYER M4 ;
      RECT 51.656 45.456 51.680 45.480 ;
    END
  END rd_out_B[39]
  PIN rd_out_A[40]
    DIRECTION OUTPUT ;
    USE SIGNAL ;
    SHAPE ABUTMENT ;
    PORT
      LAYER M4 ;
      RECT 0.000 45.888 0.024 45.912 ;
    END
  END rd_out_A[40]
  PIN rd_out_B[40]
    DIRECTION OUTPUT ;
    USE SIGNAL ;
    SHAPE ABUTMENT ;
    PORT
      LAYER M4 ;
      RECT 51.656 45.888 51.680 45.912 ;
    END
  END rd_out_B[40]
  PIN rd_out_A[41]
    DIRECTION OUTPUT ;
    USE SIGNAL ;
    SHAPE ABUTMENT ;
    PORT
      LAYER M4 ;
      RECT 0.000 46.320 0.024 46.344 ;
    END
  END rd_out_A[41]
  PIN rd_out_B[41]
    DIRECTION OUTPUT ;
    USE SIGNAL ;
    SHAPE ABUTMENT ;
    PORT
      LAYER M4 ;
      RECT 51.656 46.320 51.680 46.344 ;
    END
  END rd_out_B[41]
  PIN rd_out_A[42]
    DIRECTION OUTPUT ;
    USE SIGNAL ;
    SHAPE ABUTMENT ;
    PORT
      LAYER M4 ;
      RECT 0.000 46.752 0.024 46.776 ;
    END
  END rd_out_A[42]
  PIN rd_out_B[42]
    DIRECTION OUTPUT ;
    USE SIGNAL ;
    SHAPE ABUTMENT ;
    PORT
      LAYER M4 ;
      RECT 51.656 46.752 51.680 46.776 ;
    END
  END rd_out_B[42]
  PIN rd_out_A[43]
    DIRECTION OUTPUT ;
    USE SIGNAL ;
    SHAPE ABUTMENT ;
    PORT
      LAYER M4 ;
      RECT 0.000 47.184 0.024 47.208 ;
    END
  END rd_out_A[43]
  PIN rd_out_B[43]
    DIRECTION OUTPUT ;
    USE SIGNAL ;
    SHAPE ABUTMENT ;
    PORT
      LAYER M4 ;
      RECT 51.656 47.184 51.680 47.208 ;
    END
  END rd_out_B[43]
  PIN rd_out_A[44]
    DIRECTION OUTPUT ;
    USE SIGNAL ;
    SHAPE ABUTMENT ;
    PORT
      LAYER M4 ;
      RECT 0.000 47.616 0.024 47.640 ;
    END
  END rd_out_A[44]
  PIN rd_out_B[44]
    DIRECTION OUTPUT ;
    USE SIGNAL ;
    SHAPE ABUTMENT ;
    PORT
      LAYER M4 ;
      RECT 51.656 47.616 51.680 47.640 ;
    END
  END rd_out_B[44]
  PIN rd_out_A[45]
    DIRECTION OUTPUT ;
    USE SIGNAL ;
    SHAPE ABUTMENT ;
    PORT
      LAYER M4 ;
      RECT 0.000 48.048 0.024 48.072 ;
    END
  END rd_out_A[45]
  PIN rd_out_B[45]
    DIRECTION OUTPUT ;
    USE SIGNAL ;
    SHAPE ABUTMENT ;
    PORT
      LAYER M4 ;
      RECT 51.656 48.048 51.680 48.072 ;
    END
  END rd_out_B[45]
  PIN rd_out_A[46]
    DIRECTION OUTPUT ;
    USE SIGNAL ;
    SHAPE ABUTMENT ;
    PORT
      LAYER M4 ;
      RECT 0.000 48.480 0.024 48.504 ;
    END
  END rd_out_A[46]
  PIN rd_out_B[46]
    DIRECTION OUTPUT ;
    USE SIGNAL ;
    SHAPE ABUTMENT ;
    PORT
      LAYER M4 ;
      RECT 51.656 48.480 51.680 48.504 ;
    END
  END rd_out_B[46]
  PIN rd_out_A[47]
    DIRECTION OUTPUT ;
    USE SIGNAL ;
    SHAPE ABUTMENT ;
    PORT
      LAYER M4 ;
      RECT 0.000 48.912 0.024 48.936 ;
    END
  END rd_out_A[47]
  PIN rd_out_B[47]
    DIRECTION OUTPUT ;
    USE SIGNAL ;
    SHAPE ABUTMENT ;
    PORT
      LAYER M4 ;
      RECT 51.656 48.912 51.680 48.936 ;
    END
  END rd_out_B[47]
  PIN rd_out_A[48]
    DIRECTION OUTPUT ;
    USE SIGNAL ;
    SHAPE ABUTMENT ;
    PORT
      LAYER M4 ;
      RECT 0.000 49.344 0.024 49.368 ;
    END
  END rd_out_A[48]
  PIN rd_out_B[48]
    DIRECTION OUTPUT ;
    USE SIGNAL ;
    SHAPE ABUTMENT ;
    PORT
      LAYER M4 ;
      RECT 51.656 49.344 51.680 49.368 ;
    END
  END rd_out_B[48]
  PIN rd_out_A[49]
    DIRECTION OUTPUT ;
    USE SIGNAL ;
    SHAPE ABUTMENT ;
    PORT
      LAYER M4 ;
      RECT 0.000 49.776 0.024 49.800 ;
    END
  END rd_out_A[49]
  PIN rd_out_B[49]
    DIRECTION OUTPUT ;
    USE SIGNAL ;
    SHAPE ABUTMENT ;
    PORT
      LAYER M4 ;
      RECT 51.656 49.776 51.680 49.800 ;
    END
  END rd_out_B[49]
  PIN rd_out_A[50]
    DIRECTION OUTPUT ;
    USE SIGNAL ;
    SHAPE ABUTMENT ;
    PORT
      LAYER M4 ;
      RECT 0.000 50.208 0.024 50.232 ;
    END
  END rd_out_A[50]
  PIN rd_out_B[50]
    DIRECTION OUTPUT ;
    USE SIGNAL ;
    SHAPE ABUTMENT ;
    PORT
      LAYER M4 ;
      RECT 51.656 50.208 51.680 50.232 ;
    END
  END rd_out_B[50]
  PIN rd_out_A[51]
    DIRECTION OUTPUT ;
    USE SIGNAL ;
    SHAPE ABUTMENT ;
    PORT
      LAYER M4 ;
      RECT 0.000 50.640 0.024 50.664 ;
    END
  END rd_out_A[51]
  PIN rd_out_B[51]
    DIRECTION OUTPUT ;
    USE SIGNAL ;
    SHAPE ABUTMENT ;
    PORT
      LAYER M4 ;
      RECT 51.656 50.640 51.680 50.664 ;
    END
  END rd_out_B[51]
  PIN rd_out_A[52]
    DIRECTION OUTPUT ;
    USE SIGNAL ;
    SHAPE ABUTMENT ;
    PORT
      LAYER M4 ;
      RECT 0.000 51.072 0.024 51.096 ;
    END
  END rd_out_A[52]
  PIN rd_out_B[52]
    DIRECTION OUTPUT ;
    USE SIGNAL ;
    SHAPE ABUTMENT ;
    PORT
      LAYER M4 ;
      RECT 51.656 51.072 51.680 51.096 ;
    END
  END rd_out_B[52]
  PIN rd_out_A[53]
    DIRECTION OUTPUT ;
    USE SIGNAL ;
    SHAPE ABUTMENT ;
    PORT
      LAYER M4 ;
      RECT 0.000 51.504 0.024 51.528 ;
    END
  END rd_out_A[53]
  PIN rd_out_B[53]
    DIRECTION OUTPUT ;
    USE SIGNAL ;
    SHAPE ABUTMENT ;
    PORT
      LAYER M4 ;
      RECT 51.656 51.504 51.680 51.528 ;
    END
  END rd_out_B[53]
  PIN rd_out_A[54]
    DIRECTION OUTPUT ;
    USE SIGNAL ;
    SHAPE ABUTMENT ;
    PORT
      LAYER M4 ;
      RECT 0.000 51.936 0.024 51.960 ;
    END
  END rd_out_A[54]
  PIN rd_out_B[54]
    DIRECTION OUTPUT ;
    USE SIGNAL ;
    SHAPE ABUTMENT ;
    PORT
      LAYER M4 ;
      RECT 51.656 51.936 51.680 51.960 ;
    END
  END rd_out_B[54]
  PIN rd_out_A[55]
    DIRECTION OUTPUT ;
    USE SIGNAL ;
    SHAPE ABUTMENT ;
    PORT
      LAYER M4 ;
      RECT 0.000 52.368 0.024 52.392 ;
    END
  END rd_out_A[55]
  PIN rd_out_B[55]
    DIRECTION OUTPUT ;
    USE SIGNAL ;
    SHAPE ABUTMENT ;
    PORT
      LAYER M4 ;
      RECT 51.656 52.368 51.680 52.392 ;
    END
  END rd_out_B[55]
  PIN rd_out_A[56]
    DIRECTION OUTPUT ;
    USE SIGNAL ;
    SHAPE ABUTMENT ;
    PORT
      LAYER M4 ;
      RECT 0.000 52.800 0.024 52.824 ;
    END
  END rd_out_A[56]
  PIN rd_out_B[56]
    DIRECTION OUTPUT ;
    USE SIGNAL ;
    SHAPE ABUTMENT ;
    PORT
      LAYER M4 ;
      RECT 51.656 52.800 51.680 52.824 ;
    END
  END rd_out_B[56]
  PIN rd_out_A[57]
    DIRECTION OUTPUT ;
    USE SIGNAL ;
    SHAPE ABUTMENT ;
    PORT
      LAYER M4 ;
      RECT 0.000 53.232 0.024 53.256 ;
    END
  END rd_out_A[57]
  PIN rd_out_B[57]
    DIRECTION OUTPUT ;
    USE SIGNAL ;
    SHAPE ABUTMENT ;
    PORT
      LAYER M4 ;
      RECT 51.656 53.232 51.680 53.256 ;
    END
  END rd_out_B[57]
  PIN rd_out_A[58]
    DIRECTION OUTPUT ;
    USE SIGNAL ;
    SHAPE ABUTMENT ;
    PORT
      LAYER M4 ;
      RECT 0.000 53.664 0.024 53.688 ;
    END
  END rd_out_A[58]
  PIN rd_out_B[58]
    DIRECTION OUTPUT ;
    USE SIGNAL ;
    SHAPE ABUTMENT ;
    PORT
      LAYER M4 ;
      RECT 51.656 53.664 51.680 53.688 ;
    END
  END rd_out_B[58]
  PIN rd_out_A[59]
    DIRECTION OUTPUT ;
    USE SIGNAL ;
    SHAPE ABUTMENT ;
    PORT
      LAYER M4 ;
      RECT 0.000 54.096 0.024 54.120 ;
    END
  END rd_out_A[59]
  PIN rd_out_B[59]
    DIRECTION OUTPUT ;
    USE SIGNAL ;
    SHAPE ABUTMENT ;
    PORT
      LAYER M4 ;
      RECT 51.656 54.096 51.680 54.120 ;
    END
  END rd_out_B[59]
  PIN rd_out_A[60]
    DIRECTION OUTPUT ;
    USE SIGNAL ;
    SHAPE ABUTMENT ;
    PORT
      LAYER M4 ;
      RECT 0.000 54.528 0.024 54.552 ;
    END
  END rd_out_A[60]
  PIN rd_out_B[60]
    DIRECTION OUTPUT ;
    USE SIGNAL ;
    SHAPE ABUTMENT ;
    PORT
      LAYER M4 ;
      RECT 51.656 54.528 51.680 54.552 ;
    END
  END rd_out_B[60]
  PIN rd_out_A[61]
    DIRECTION OUTPUT ;
    USE SIGNAL ;
    SHAPE ABUTMENT ;
    PORT
      LAYER M4 ;
      RECT 0.000 54.960 0.024 54.984 ;
    END
  END rd_out_A[61]
  PIN rd_out_B[61]
    DIRECTION OUTPUT ;
    USE SIGNAL ;
    SHAPE ABUTMENT ;
    PORT
      LAYER M4 ;
      RECT 51.656 54.960 51.680 54.984 ;
    END
  END rd_out_B[61]
  PIN rd_out_A[62]
    DIRECTION OUTPUT ;
    USE SIGNAL ;
    SHAPE ABUTMENT ;
    PORT
      LAYER M4 ;
      RECT 0.000 55.392 0.024 55.416 ;
    END
  END rd_out_A[62]
  PIN rd_out_B[62]
    DIRECTION OUTPUT ;
    USE SIGNAL ;
    SHAPE ABUTMENT ;
    PORT
      LAYER M4 ;
      RECT 51.656 55.392 51.680 55.416 ;
    END
  END rd_out_B[62]
  PIN rd_out_A[63]
    DIRECTION OUTPUT ;
    USE SIGNAL ;
    SHAPE ABUTMENT ;
    PORT
      LAYER M4 ;
      RECT 0.000 55.824 0.024 55.848 ;
    END
  END rd_out_A[63]
  PIN rd_out_B[63]
    DIRECTION OUTPUT ;
    USE SIGNAL ;
    SHAPE ABUTMENT ;
    PORT
      LAYER M4 ;
      RECT 51.656 55.824 51.680 55.848 ;
    END
  END rd_out_B[63]
  PIN wd_in_A[0]
    DIRECTION INPUT ;
    USE SIGNAL ;
    SHAPE ABUTMENT ;
    PORT
      LAYER M4 ;
      RECT 0.000 57.168 0.024 57.192 ;
    END
  END wd_in_A[0]
  PIN wd_in_B[0]
    DIRECTION INPUT ;
    USE SIGNAL ;
    SHAPE ABUTMENT ;
    PORT
      LAYER M4 ;
      RECT 51.656 57.168 51.680 57.192 ;
    END
  END wd_in_B[0]
  PIN wd_in_A[1]
    DIRECTION INPUT ;
    USE SIGNAL ;
    SHAPE ABUTMENT ;
    PORT
      LAYER M4 ;
      RECT 0.000 57.600 0.024 57.624 ;
    END
  END wd_in_A[1]
  PIN wd_in_B[1]
    DIRECTION INPUT ;
    USE SIGNAL ;
    SHAPE ABUTMENT ;
    PORT
      LAYER M4 ;
      RECT 51.656 57.600 51.680 57.624 ;
    END
  END wd_in_B[1]
  PIN wd_in_A[2]
    DIRECTION INPUT ;
    USE SIGNAL ;
    SHAPE ABUTMENT ;
    PORT
      LAYER M4 ;
      RECT 0.000 58.032 0.024 58.056 ;
    END
  END wd_in_A[2]
  PIN wd_in_B[2]
    DIRECTION INPUT ;
    USE SIGNAL ;
    SHAPE ABUTMENT ;
    PORT
      LAYER M4 ;
      RECT 51.656 58.032 51.680 58.056 ;
    END
  END wd_in_B[2]
  PIN wd_in_A[3]
    DIRECTION INPUT ;
    USE SIGNAL ;
    SHAPE ABUTMENT ;
    PORT
      LAYER M4 ;
      RECT 0.000 58.464 0.024 58.488 ;
    END
  END wd_in_A[3]
  PIN wd_in_B[3]
    DIRECTION INPUT ;
    USE SIGNAL ;
    SHAPE ABUTMENT ;
    PORT
      LAYER M4 ;
      RECT 51.656 58.464 51.680 58.488 ;
    END
  END wd_in_B[3]
  PIN wd_in_A[4]
    DIRECTION INPUT ;
    USE SIGNAL ;
    SHAPE ABUTMENT ;
    PORT
      LAYER M4 ;
      RECT 0.000 58.896 0.024 58.920 ;
    END
  END wd_in_A[4]
  PIN wd_in_B[4]
    DIRECTION INPUT ;
    USE SIGNAL ;
    SHAPE ABUTMENT ;
    PORT
      LAYER M4 ;
      RECT 51.656 58.896 51.680 58.920 ;
    END
  END wd_in_B[4]
  PIN wd_in_A[5]
    DIRECTION INPUT ;
    USE SIGNAL ;
    SHAPE ABUTMENT ;
    PORT
      LAYER M4 ;
      RECT 0.000 59.328 0.024 59.352 ;
    END
  END wd_in_A[5]
  PIN wd_in_B[5]
    DIRECTION INPUT ;
    USE SIGNAL ;
    SHAPE ABUTMENT ;
    PORT
      LAYER M4 ;
      RECT 51.656 59.328 51.680 59.352 ;
    END
  END wd_in_B[5]
  PIN wd_in_A[6]
    DIRECTION INPUT ;
    USE SIGNAL ;
    SHAPE ABUTMENT ;
    PORT
      LAYER M4 ;
      RECT 0.000 59.760 0.024 59.784 ;
    END
  END wd_in_A[6]
  PIN wd_in_B[6]
    DIRECTION INPUT ;
    USE SIGNAL ;
    SHAPE ABUTMENT ;
    PORT
      LAYER M4 ;
      RECT 51.656 59.760 51.680 59.784 ;
    END
  END wd_in_B[6]
  PIN wd_in_A[7]
    DIRECTION INPUT ;
    USE SIGNAL ;
    SHAPE ABUTMENT ;
    PORT
      LAYER M4 ;
      RECT 0.000 60.192 0.024 60.216 ;
    END
  END wd_in_A[7]
  PIN wd_in_B[7]
    DIRECTION INPUT ;
    USE SIGNAL ;
    SHAPE ABUTMENT ;
    PORT
      LAYER M4 ;
      RECT 51.656 60.192 51.680 60.216 ;
    END
  END wd_in_B[7]
  PIN wd_in_A[8]
    DIRECTION INPUT ;
    USE SIGNAL ;
    SHAPE ABUTMENT ;
    PORT
      LAYER M4 ;
      RECT 0.000 60.624 0.024 60.648 ;
    END
  END wd_in_A[8]
  PIN wd_in_B[8]
    DIRECTION INPUT ;
    USE SIGNAL ;
    SHAPE ABUTMENT ;
    PORT
      LAYER M4 ;
      RECT 51.656 60.624 51.680 60.648 ;
    END
  END wd_in_B[8]
  PIN wd_in_A[9]
    DIRECTION INPUT ;
    USE SIGNAL ;
    SHAPE ABUTMENT ;
    PORT
      LAYER M4 ;
      RECT 0.000 61.056 0.024 61.080 ;
    END
  END wd_in_A[9]
  PIN wd_in_B[9]
    DIRECTION INPUT ;
    USE SIGNAL ;
    SHAPE ABUTMENT ;
    PORT
      LAYER M4 ;
      RECT 51.656 61.056 51.680 61.080 ;
    END
  END wd_in_B[9]
  PIN wd_in_A[10]
    DIRECTION INPUT ;
    USE SIGNAL ;
    SHAPE ABUTMENT ;
    PORT
      LAYER M4 ;
      RECT 0.000 61.488 0.024 61.512 ;
    END
  END wd_in_A[10]
  PIN wd_in_B[10]
    DIRECTION INPUT ;
    USE SIGNAL ;
    SHAPE ABUTMENT ;
    PORT
      LAYER M4 ;
      RECT 51.656 61.488 51.680 61.512 ;
    END
  END wd_in_B[10]
  PIN wd_in_A[11]
    DIRECTION INPUT ;
    USE SIGNAL ;
    SHAPE ABUTMENT ;
    PORT
      LAYER M4 ;
      RECT 0.000 61.920 0.024 61.944 ;
    END
  END wd_in_A[11]
  PIN wd_in_B[11]
    DIRECTION INPUT ;
    USE SIGNAL ;
    SHAPE ABUTMENT ;
    PORT
      LAYER M4 ;
      RECT 51.656 61.920 51.680 61.944 ;
    END
  END wd_in_B[11]
  PIN wd_in_A[12]
    DIRECTION INPUT ;
    USE SIGNAL ;
    SHAPE ABUTMENT ;
    PORT
      LAYER M4 ;
      RECT 0.000 62.352 0.024 62.376 ;
    END
  END wd_in_A[12]
  PIN wd_in_B[12]
    DIRECTION INPUT ;
    USE SIGNAL ;
    SHAPE ABUTMENT ;
    PORT
      LAYER M4 ;
      RECT 51.656 62.352 51.680 62.376 ;
    END
  END wd_in_B[12]
  PIN wd_in_A[13]
    DIRECTION INPUT ;
    USE SIGNAL ;
    SHAPE ABUTMENT ;
    PORT
      LAYER M4 ;
      RECT 0.000 62.784 0.024 62.808 ;
    END
  END wd_in_A[13]
  PIN wd_in_B[13]
    DIRECTION INPUT ;
    USE SIGNAL ;
    SHAPE ABUTMENT ;
    PORT
      LAYER M4 ;
      RECT 51.656 62.784 51.680 62.808 ;
    END
  END wd_in_B[13]
  PIN wd_in_A[14]
    DIRECTION INPUT ;
    USE SIGNAL ;
    SHAPE ABUTMENT ;
    PORT
      LAYER M4 ;
      RECT 0.000 63.216 0.024 63.240 ;
    END
  END wd_in_A[14]
  PIN wd_in_B[14]
    DIRECTION INPUT ;
    USE SIGNAL ;
    SHAPE ABUTMENT ;
    PORT
      LAYER M4 ;
      RECT 51.656 63.216 51.680 63.240 ;
    END
  END wd_in_B[14]
  PIN wd_in_A[15]
    DIRECTION INPUT ;
    USE SIGNAL ;
    SHAPE ABUTMENT ;
    PORT
      LAYER M4 ;
      RECT 0.000 63.648 0.024 63.672 ;
    END
  END wd_in_A[15]
  PIN wd_in_B[15]
    DIRECTION INPUT ;
    USE SIGNAL ;
    SHAPE ABUTMENT ;
    PORT
      LAYER M4 ;
      RECT 51.656 63.648 51.680 63.672 ;
    END
  END wd_in_B[15]
  PIN wd_in_A[16]
    DIRECTION INPUT ;
    USE SIGNAL ;
    SHAPE ABUTMENT ;
    PORT
      LAYER M4 ;
      RECT 0.000 64.080 0.024 64.104 ;
    END
  END wd_in_A[16]
  PIN wd_in_B[16]
    DIRECTION INPUT ;
    USE SIGNAL ;
    SHAPE ABUTMENT ;
    PORT
      LAYER M4 ;
      RECT 51.656 64.080 51.680 64.104 ;
    END
  END wd_in_B[16]
  PIN wd_in_A[17]
    DIRECTION INPUT ;
    USE SIGNAL ;
    SHAPE ABUTMENT ;
    PORT
      LAYER M4 ;
      RECT 0.000 64.512 0.024 64.536 ;
    END
  END wd_in_A[17]
  PIN wd_in_B[17]
    DIRECTION INPUT ;
    USE SIGNAL ;
    SHAPE ABUTMENT ;
    PORT
      LAYER M4 ;
      RECT 51.656 64.512 51.680 64.536 ;
    END
  END wd_in_B[17]
  PIN wd_in_A[18]
    DIRECTION INPUT ;
    USE SIGNAL ;
    SHAPE ABUTMENT ;
    PORT
      LAYER M4 ;
      RECT 0.000 64.944 0.024 64.968 ;
    END
  END wd_in_A[18]
  PIN wd_in_B[18]
    DIRECTION INPUT ;
    USE SIGNAL ;
    SHAPE ABUTMENT ;
    PORT
      LAYER M4 ;
      RECT 51.656 64.944 51.680 64.968 ;
    END
  END wd_in_B[18]
  PIN wd_in_A[19]
    DIRECTION INPUT ;
    USE SIGNAL ;
    SHAPE ABUTMENT ;
    PORT
      LAYER M4 ;
      RECT 0.000 65.376 0.024 65.400 ;
    END
  END wd_in_A[19]
  PIN wd_in_B[19]
    DIRECTION INPUT ;
    USE SIGNAL ;
    SHAPE ABUTMENT ;
    PORT
      LAYER M4 ;
      RECT 51.656 65.376 51.680 65.400 ;
    END
  END wd_in_B[19]
  PIN wd_in_A[20]
    DIRECTION INPUT ;
    USE SIGNAL ;
    SHAPE ABUTMENT ;
    PORT
      LAYER M4 ;
      RECT 0.000 65.808 0.024 65.832 ;
    END
  END wd_in_A[20]
  PIN wd_in_B[20]
    DIRECTION INPUT ;
    USE SIGNAL ;
    SHAPE ABUTMENT ;
    PORT
      LAYER M4 ;
      RECT 51.656 65.808 51.680 65.832 ;
    END
  END wd_in_B[20]
  PIN wd_in_A[21]
    DIRECTION INPUT ;
    USE SIGNAL ;
    SHAPE ABUTMENT ;
    PORT
      LAYER M4 ;
      RECT 0.000 66.240 0.024 66.264 ;
    END
  END wd_in_A[21]
  PIN wd_in_B[21]
    DIRECTION INPUT ;
    USE SIGNAL ;
    SHAPE ABUTMENT ;
    PORT
      LAYER M4 ;
      RECT 51.656 66.240 51.680 66.264 ;
    END
  END wd_in_B[21]
  PIN wd_in_A[22]
    DIRECTION INPUT ;
    USE SIGNAL ;
    SHAPE ABUTMENT ;
    PORT
      LAYER M4 ;
      RECT 0.000 66.672 0.024 66.696 ;
    END
  END wd_in_A[22]
  PIN wd_in_B[22]
    DIRECTION INPUT ;
    USE SIGNAL ;
    SHAPE ABUTMENT ;
    PORT
      LAYER M4 ;
      RECT 51.656 66.672 51.680 66.696 ;
    END
  END wd_in_B[22]
  PIN wd_in_A[23]
    DIRECTION INPUT ;
    USE SIGNAL ;
    SHAPE ABUTMENT ;
    PORT
      LAYER M4 ;
      RECT 0.000 67.104 0.024 67.128 ;
    END
  END wd_in_A[23]
  PIN wd_in_B[23]
    DIRECTION INPUT ;
    USE SIGNAL ;
    SHAPE ABUTMENT ;
    PORT
      LAYER M4 ;
      RECT 51.656 67.104 51.680 67.128 ;
    END
  END wd_in_B[23]
  PIN wd_in_A[24]
    DIRECTION INPUT ;
    USE SIGNAL ;
    SHAPE ABUTMENT ;
    PORT
      LAYER M4 ;
      RECT 0.000 67.536 0.024 67.560 ;
    END
  END wd_in_A[24]
  PIN wd_in_B[24]
    DIRECTION INPUT ;
    USE SIGNAL ;
    SHAPE ABUTMENT ;
    PORT
      LAYER M4 ;
      RECT 51.656 67.536 51.680 67.560 ;
    END
  END wd_in_B[24]
  PIN wd_in_A[25]
    DIRECTION INPUT ;
    USE SIGNAL ;
    SHAPE ABUTMENT ;
    PORT
      LAYER M4 ;
      RECT 0.000 67.968 0.024 67.992 ;
    END
  END wd_in_A[25]
  PIN wd_in_B[25]
    DIRECTION INPUT ;
    USE SIGNAL ;
    SHAPE ABUTMENT ;
    PORT
      LAYER M4 ;
      RECT 51.656 67.968 51.680 67.992 ;
    END
  END wd_in_B[25]
  PIN wd_in_A[26]
    DIRECTION INPUT ;
    USE SIGNAL ;
    SHAPE ABUTMENT ;
    PORT
      LAYER M4 ;
      RECT 0.000 68.400 0.024 68.424 ;
    END
  END wd_in_A[26]
  PIN wd_in_B[26]
    DIRECTION INPUT ;
    USE SIGNAL ;
    SHAPE ABUTMENT ;
    PORT
      LAYER M4 ;
      RECT 51.656 68.400 51.680 68.424 ;
    END
  END wd_in_B[26]
  PIN wd_in_A[27]
    DIRECTION INPUT ;
    USE SIGNAL ;
    SHAPE ABUTMENT ;
    PORT
      LAYER M4 ;
      RECT 0.000 68.832 0.024 68.856 ;
    END
  END wd_in_A[27]
  PIN wd_in_B[27]
    DIRECTION INPUT ;
    USE SIGNAL ;
    SHAPE ABUTMENT ;
    PORT
      LAYER M4 ;
      RECT 51.656 68.832 51.680 68.856 ;
    END
  END wd_in_B[27]
  PIN wd_in_A[28]
    DIRECTION INPUT ;
    USE SIGNAL ;
    SHAPE ABUTMENT ;
    PORT
      LAYER M4 ;
      RECT 0.000 69.264 0.024 69.288 ;
    END
  END wd_in_A[28]
  PIN wd_in_B[28]
    DIRECTION INPUT ;
    USE SIGNAL ;
    SHAPE ABUTMENT ;
    PORT
      LAYER M4 ;
      RECT 51.656 69.264 51.680 69.288 ;
    END
  END wd_in_B[28]
  PIN wd_in_A[29]
    DIRECTION INPUT ;
    USE SIGNAL ;
    SHAPE ABUTMENT ;
    PORT
      LAYER M4 ;
      RECT 0.000 69.696 0.024 69.720 ;
    END
  END wd_in_A[29]
  PIN wd_in_B[29]
    DIRECTION INPUT ;
    USE SIGNAL ;
    SHAPE ABUTMENT ;
    PORT
      LAYER M4 ;
      RECT 51.656 69.696 51.680 69.720 ;
    END
  END wd_in_B[29]
  PIN wd_in_A[30]
    DIRECTION INPUT ;
    USE SIGNAL ;
    SHAPE ABUTMENT ;
    PORT
      LAYER M4 ;
      RECT 0.000 70.128 0.024 70.152 ;
    END
  END wd_in_A[30]
  PIN wd_in_B[30]
    DIRECTION INPUT ;
    USE SIGNAL ;
    SHAPE ABUTMENT ;
    PORT
      LAYER M4 ;
      RECT 51.656 70.128 51.680 70.152 ;
    END
  END wd_in_B[30]
  PIN wd_in_A[31]
    DIRECTION INPUT ;
    USE SIGNAL ;
    SHAPE ABUTMENT ;
    PORT
      LAYER M4 ;
      RECT 0.000 70.560 0.024 70.584 ;
    END
  END wd_in_A[31]
  PIN wd_in_B[31]
    DIRECTION INPUT ;
    USE SIGNAL ;
    SHAPE ABUTMENT ;
    PORT
      LAYER M4 ;
      RECT 51.656 70.560 51.680 70.584 ;
    END
  END wd_in_B[31]
  PIN wd_in_A[32]
    DIRECTION INPUT ;
    USE SIGNAL ;
    SHAPE ABUTMENT ;
    PORT
      LAYER M4 ;
      RECT 0.000 70.992 0.024 71.016 ;
    END
  END wd_in_A[32]
  PIN wd_in_B[32]
    DIRECTION INPUT ;
    USE SIGNAL ;
    SHAPE ABUTMENT ;
    PORT
      LAYER M4 ;
      RECT 51.656 70.992 51.680 71.016 ;
    END
  END wd_in_B[32]
  PIN wd_in_A[33]
    DIRECTION INPUT ;
    USE SIGNAL ;
    SHAPE ABUTMENT ;
    PORT
      LAYER M4 ;
      RECT 0.000 71.424 0.024 71.448 ;
    END
  END wd_in_A[33]
  PIN wd_in_B[33]
    DIRECTION INPUT ;
    USE SIGNAL ;
    SHAPE ABUTMENT ;
    PORT
      LAYER M4 ;
      RECT 51.656 71.424 51.680 71.448 ;
    END
  END wd_in_B[33]
  PIN wd_in_A[34]
    DIRECTION INPUT ;
    USE SIGNAL ;
    SHAPE ABUTMENT ;
    PORT
      LAYER M4 ;
      RECT 0.000 71.856 0.024 71.880 ;
    END
  END wd_in_A[34]
  PIN wd_in_B[34]
    DIRECTION INPUT ;
    USE SIGNAL ;
    SHAPE ABUTMENT ;
    PORT
      LAYER M4 ;
      RECT 51.656 71.856 51.680 71.880 ;
    END
  END wd_in_B[34]
  PIN wd_in_A[35]
    DIRECTION INPUT ;
    USE SIGNAL ;
    SHAPE ABUTMENT ;
    PORT
      LAYER M4 ;
      RECT 0.000 72.288 0.024 72.312 ;
    END
  END wd_in_A[35]
  PIN wd_in_B[35]
    DIRECTION INPUT ;
    USE SIGNAL ;
    SHAPE ABUTMENT ;
    PORT
      LAYER M4 ;
      RECT 51.656 72.288 51.680 72.312 ;
    END
  END wd_in_B[35]
  PIN wd_in_A[36]
    DIRECTION INPUT ;
    USE SIGNAL ;
    SHAPE ABUTMENT ;
    PORT
      LAYER M4 ;
      RECT 0.000 72.720 0.024 72.744 ;
    END
  END wd_in_A[36]
  PIN wd_in_B[36]
    DIRECTION INPUT ;
    USE SIGNAL ;
    SHAPE ABUTMENT ;
    PORT
      LAYER M4 ;
      RECT 51.656 72.720 51.680 72.744 ;
    END
  END wd_in_B[36]
  PIN wd_in_A[37]
    DIRECTION INPUT ;
    USE SIGNAL ;
    SHAPE ABUTMENT ;
    PORT
      LAYER M4 ;
      RECT 0.000 73.152 0.024 73.176 ;
    END
  END wd_in_A[37]
  PIN wd_in_B[37]
    DIRECTION INPUT ;
    USE SIGNAL ;
    SHAPE ABUTMENT ;
    PORT
      LAYER M4 ;
      RECT 51.656 73.152 51.680 73.176 ;
    END
  END wd_in_B[37]
  PIN wd_in_A[38]
    DIRECTION INPUT ;
    USE SIGNAL ;
    SHAPE ABUTMENT ;
    PORT
      LAYER M4 ;
      RECT 0.000 73.584 0.024 73.608 ;
    END
  END wd_in_A[38]
  PIN wd_in_B[38]
    DIRECTION INPUT ;
    USE SIGNAL ;
    SHAPE ABUTMENT ;
    PORT
      LAYER M4 ;
      RECT 51.656 73.584 51.680 73.608 ;
    END
  END wd_in_B[38]
  PIN wd_in_A[39]
    DIRECTION INPUT ;
    USE SIGNAL ;
    SHAPE ABUTMENT ;
    PORT
      LAYER M4 ;
      RECT 0.000 74.016 0.024 74.040 ;
    END
  END wd_in_A[39]
  PIN wd_in_B[39]
    DIRECTION INPUT ;
    USE SIGNAL ;
    SHAPE ABUTMENT ;
    PORT
      LAYER M4 ;
      RECT 51.656 74.016 51.680 74.040 ;
    END
  END wd_in_B[39]
  PIN wd_in_A[40]
    DIRECTION INPUT ;
    USE SIGNAL ;
    SHAPE ABUTMENT ;
    PORT
      LAYER M4 ;
      RECT 0.000 74.448 0.024 74.472 ;
    END
  END wd_in_A[40]
  PIN wd_in_B[40]
    DIRECTION INPUT ;
    USE SIGNAL ;
    SHAPE ABUTMENT ;
    PORT
      LAYER M4 ;
      RECT 51.656 74.448 51.680 74.472 ;
    END
  END wd_in_B[40]
  PIN wd_in_A[41]
    DIRECTION INPUT ;
    USE SIGNAL ;
    SHAPE ABUTMENT ;
    PORT
      LAYER M4 ;
      RECT 0.000 74.880 0.024 74.904 ;
    END
  END wd_in_A[41]
  PIN wd_in_B[41]
    DIRECTION INPUT ;
    USE SIGNAL ;
    SHAPE ABUTMENT ;
    PORT
      LAYER M4 ;
      RECT 51.656 74.880 51.680 74.904 ;
    END
  END wd_in_B[41]
  PIN wd_in_A[42]
    DIRECTION INPUT ;
    USE SIGNAL ;
    SHAPE ABUTMENT ;
    PORT
      LAYER M4 ;
      RECT 0.000 75.312 0.024 75.336 ;
    END
  END wd_in_A[42]
  PIN wd_in_B[42]
    DIRECTION INPUT ;
    USE SIGNAL ;
    SHAPE ABUTMENT ;
    PORT
      LAYER M4 ;
      RECT 51.656 75.312 51.680 75.336 ;
    END
  END wd_in_B[42]
  PIN wd_in_A[43]
    DIRECTION INPUT ;
    USE SIGNAL ;
    SHAPE ABUTMENT ;
    PORT
      LAYER M4 ;
      RECT 0.000 75.744 0.024 75.768 ;
    END
  END wd_in_A[43]
  PIN wd_in_B[43]
    DIRECTION INPUT ;
    USE SIGNAL ;
    SHAPE ABUTMENT ;
    PORT
      LAYER M4 ;
      RECT 51.656 75.744 51.680 75.768 ;
    END
  END wd_in_B[43]
  PIN wd_in_A[44]
    DIRECTION INPUT ;
    USE SIGNAL ;
    SHAPE ABUTMENT ;
    PORT
      LAYER M4 ;
      RECT 0.000 76.176 0.024 76.200 ;
    END
  END wd_in_A[44]
  PIN wd_in_B[44]
    DIRECTION INPUT ;
    USE SIGNAL ;
    SHAPE ABUTMENT ;
    PORT
      LAYER M4 ;
      RECT 51.656 76.176 51.680 76.200 ;
    END
  END wd_in_B[44]
  PIN wd_in_A[45]
    DIRECTION INPUT ;
    USE SIGNAL ;
    SHAPE ABUTMENT ;
    PORT
      LAYER M4 ;
      RECT 0.000 76.608 0.024 76.632 ;
    END
  END wd_in_A[45]
  PIN wd_in_B[45]
    DIRECTION INPUT ;
    USE SIGNAL ;
    SHAPE ABUTMENT ;
    PORT
      LAYER M4 ;
      RECT 51.656 76.608 51.680 76.632 ;
    END
  END wd_in_B[45]
  PIN wd_in_A[46]
    DIRECTION INPUT ;
    USE SIGNAL ;
    SHAPE ABUTMENT ;
    PORT
      LAYER M4 ;
      RECT 0.000 77.040 0.024 77.064 ;
    END
  END wd_in_A[46]
  PIN wd_in_B[46]
    DIRECTION INPUT ;
    USE SIGNAL ;
    SHAPE ABUTMENT ;
    PORT
      LAYER M4 ;
      RECT 51.656 77.040 51.680 77.064 ;
    END
  END wd_in_B[46]
  PIN wd_in_A[47]
    DIRECTION INPUT ;
    USE SIGNAL ;
    SHAPE ABUTMENT ;
    PORT
      LAYER M4 ;
      RECT 0.000 77.472 0.024 77.496 ;
    END
  END wd_in_A[47]
  PIN wd_in_B[47]
    DIRECTION INPUT ;
    USE SIGNAL ;
    SHAPE ABUTMENT ;
    PORT
      LAYER M4 ;
      RECT 51.656 77.472 51.680 77.496 ;
    END
  END wd_in_B[47]
  PIN wd_in_A[48]
    DIRECTION INPUT ;
    USE SIGNAL ;
    SHAPE ABUTMENT ;
    PORT
      LAYER M4 ;
      RECT 0.000 77.904 0.024 77.928 ;
    END
  END wd_in_A[48]
  PIN wd_in_B[48]
    DIRECTION INPUT ;
    USE SIGNAL ;
    SHAPE ABUTMENT ;
    PORT
      LAYER M4 ;
      RECT 51.656 77.904 51.680 77.928 ;
    END
  END wd_in_B[48]
  PIN wd_in_A[49]
    DIRECTION INPUT ;
    USE SIGNAL ;
    SHAPE ABUTMENT ;
    PORT
      LAYER M4 ;
      RECT 0.000 78.336 0.024 78.360 ;
    END
  END wd_in_A[49]
  PIN wd_in_B[49]
    DIRECTION INPUT ;
    USE SIGNAL ;
    SHAPE ABUTMENT ;
    PORT
      LAYER M4 ;
      RECT 51.656 78.336 51.680 78.360 ;
    END
  END wd_in_B[49]
  PIN wd_in_A[50]
    DIRECTION INPUT ;
    USE SIGNAL ;
    SHAPE ABUTMENT ;
    PORT
      LAYER M4 ;
      RECT 0.000 78.768 0.024 78.792 ;
    END
  END wd_in_A[50]
  PIN wd_in_B[50]
    DIRECTION INPUT ;
    USE SIGNAL ;
    SHAPE ABUTMENT ;
    PORT
      LAYER M4 ;
      RECT 51.656 78.768 51.680 78.792 ;
    END
  END wd_in_B[50]
  PIN wd_in_A[51]
    DIRECTION INPUT ;
    USE SIGNAL ;
    SHAPE ABUTMENT ;
    PORT
      LAYER M4 ;
      RECT 0.000 79.200 0.024 79.224 ;
    END
  END wd_in_A[51]
  PIN wd_in_B[51]
    DIRECTION INPUT ;
    USE SIGNAL ;
    SHAPE ABUTMENT ;
    PORT
      LAYER M4 ;
      RECT 51.656 79.200 51.680 79.224 ;
    END
  END wd_in_B[51]
  PIN wd_in_A[52]
    DIRECTION INPUT ;
    USE SIGNAL ;
    SHAPE ABUTMENT ;
    PORT
      LAYER M4 ;
      RECT 0.000 79.632 0.024 79.656 ;
    END
  END wd_in_A[52]
  PIN wd_in_B[52]
    DIRECTION INPUT ;
    USE SIGNAL ;
    SHAPE ABUTMENT ;
    PORT
      LAYER M4 ;
      RECT 51.656 79.632 51.680 79.656 ;
    END
  END wd_in_B[52]
  PIN wd_in_A[53]
    DIRECTION INPUT ;
    USE SIGNAL ;
    SHAPE ABUTMENT ;
    PORT
      LAYER M4 ;
      RECT 0.000 80.064 0.024 80.088 ;
    END
  END wd_in_A[53]
  PIN wd_in_B[53]
    DIRECTION INPUT ;
    USE SIGNAL ;
    SHAPE ABUTMENT ;
    PORT
      LAYER M4 ;
      RECT 51.656 80.064 51.680 80.088 ;
    END
  END wd_in_B[53]
  PIN wd_in_A[54]
    DIRECTION INPUT ;
    USE SIGNAL ;
    SHAPE ABUTMENT ;
    PORT
      LAYER M4 ;
      RECT 0.000 80.496 0.024 80.520 ;
    END
  END wd_in_A[54]
  PIN wd_in_B[54]
    DIRECTION INPUT ;
    USE SIGNAL ;
    SHAPE ABUTMENT ;
    PORT
      LAYER M4 ;
      RECT 51.656 80.496 51.680 80.520 ;
    END
  END wd_in_B[54]
  PIN wd_in_A[55]
    DIRECTION INPUT ;
    USE SIGNAL ;
    SHAPE ABUTMENT ;
    PORT
      LAYER M4 ;
      RECT 0.000 80.928 0.024 80.952 ;
    END
  END wd_in_A[55]
  PIN wd_in_B[55]
    DIRECTION INPUT ;
    USE SIGNAL ;
    SHAPE ABUTMENT ;
    PORT
      LAYER M4 ;
      RECT 51.656 80.928 51.680 80.952 ;
    END
  END wd_in_B[55]
  PIN wd_in_A[56]
    DIRECTION INPUT ;
    USE SIGNAL ;
    SHAPE ABUTMENT ;
    PORT
      LAYER M4 ;
      RECT 0.000 81.360 0.024 81.384 ;
    END
  END wd_in_A[56]
  PIN wd_in_B[56]
    DIRECTION INPUT ;
    USE SIGNAL ;
    SHAPE ABUTMENT ;
    PORT
      LAYER M4 ;
      RECT 51.656 81.360 51.680 81.384 ;
    END
  END wd_in_B[56]
  PIN wd_in_A[57]
    DIRECTION INPUT ;
    USE SIGNAL ;
    SHAPE ABUTMENT ;
    PORT
      LAYER M4 ;
      RECT 0.000 81.792 0.024 81.816 ;
    END
  END wd_in_A[57]
  PIN wd_in_B[57]
    DIRECTION INPUT ;
    USE SIGNAL ;
    SHAPE ABUTMENT ;
    PORT
      LAYER M4 ;
      RECT 51.656 81.792 51.680 81.816 ;
    END
  END wd_in_B[57]
  PIN wd_in_A[58]
    DIRECTION INPUT ;
    USE SIGNAL ;
    SHAPE ABUTMENT ;
    PORT
      LAYER M4 ;
      RECT 0.000 82.224 0.024 82.248 ;
    END
  END wd_in_A[58]
  PIN wd_in_B[58]
    DIRECTION INPUT ;
    USE SIGNAL ;
    SHAPE ABUTMENT ;
    PORT
      LAYER M4 ;
      RECT 51.656 82.224 51.680 82.248 ;
    END
  END wd_in_B[58]
  PIN wd_in_A[59]
    DIRECTION INPUT ;
    USE SIGNAL ;
    SHAPE ABUTMENT ;
    PORT
      LAYER M4 ;
      RECT 0.000 82.656 0.024 82.680 ;
    END
  END wd_in_A[59]
  PIN wd_in_B[59]
    DIRECTION INPUT ;
    USE SIGNAL ;
    SHAPE ABUTMENT ;
    PORT
      LAYER M4 ;
      RECT 51.656 82.656 51.680 82.680 ;
    END
  END wd_in_B[59]
  PIN wd_in_A[60]
    DIRECTION INPUT ;
    USE SIGNAL ;
    SHAPE ABUTMENT ;
    PORT
      LAYER M4 ;
      RECT 0.000 83.088 0.024 83.112 ;
    END
  END wd_in_A[60]
  PIN wd_in_B[60]
    DIRECTION INPUT ;
    USE SIGNAL ;
    SHAPE ABUTMENT ;
    PORT
      LAYER M4 ;
      RECT 51.656 83.088 51.680 83.112 ;
    END
  END wd_in_B[60]
  PIN wd_in_A[61]
    DIRECTION INPUT ;
    USE SIGNAL ;
    SHAPE ABUTMENT ;
    PORT
      LAYER M4 ;
      RECT 0.000 83.520 0.024 83.544 ;
    END
  END wd_in_A[61]
  PIN wd_in_B[61]
    DIRECTION INPUT ;
    USE SIGNAL ;
    SHAPE ABUTMENT ;
    PORT
      LAYER M4 ;
      RECT 51.656 83.520 51.680 83.544 ;
    END
  END wd_in_B[61]
  PIN wd_in_A[62]
    DIRECTION INPUT ;
    USE SIGNAL ;
    SHAPE ABUTMENT ;
    PORT
      LAYER M4 ;
      RECT 0.000 83.952 0.024 83.976 ;
    END
  END wd_in_A[62]
  PIN wd_in_B[62]
    DIRECTION INPUT ;
    USE SIGNAL ;
    SHAPE ABUTMENT ;
    PORT
      LAYER M4 ;
      RECT 51.656 83.952 51.680 83.976 ;
    END
  END wd_in_B[62]
  PIN wd_in_A[63]
    DIRECTION INPUT ;
    USE SIGNAL ;
    SHAPE ABUTMENT ;
    PORT
      LAYER M4 ;
      RECT 0.000 84.384 0.024 84.408 ;
    END
  END wd_in_A[63]
  PIN wd_in_B[63]
    DIRECTION INPUT ;
    USE SIGNAL ;
    SHAPE ABUTMENT ;
    PORT
      LAYER M4 ;
      RECT 51.656 84.384 51.680 84.408 ;
    END
  END wd_in_B[63]
  PIN addr_in_A[0]
    DIRECTION INPUT ;
    USE SIGNAL ;
    SHAPE ABUTMENT ;
    PORT
      LAYER M4 ;
      RECT 0.000 85.728 0.024 85.752 ;
    END
  END addr_in_A[0]
  PIN addr_in_B[0]
    DIRECTION INPUT ;
    USE SIGNAL ;
    SHAPE ABUTMENT ;
    PORT
      LAYER M4 ;
      RECT 51.656 85.728 51.680 85.752 ;
    END
  END addr_in_B[0]
  PIN addr_in_A[1]
    DIRECTION INPUT ;
    USE SIGNAL ;
    SHAPE ABUTMENT ;
    PORT
      LAYER M4 ;
      RECT 0.000 86.160 0.024 86.184 ;
    END
  END addr_in_A[1]
  PIN addr_in_B[1]
    DIRECTION INPUT ;
    USE SIGNAL ;
    SHAPE ABUTMENT ;
    PORT
      LAYER M4 ;
      RECT 51.656 86.160 51.680 86.184 ;
    END
  END addr_in_B[1]
  PIN addr_in_A[2]
    DIRECTION INPUT ;
    USE SIGNAL ;
    SHAPE ABUTMENT ;
    PORT
      LAYER M4 ;
      RECT 0.000 86.592 0.024 86.616 ;
    END
  END addr_in_A[2]
  PIN addr_in_B[2]
    DIRECTION INPUT ;
    USE SIGNAL ;
    SHAPE ABUTMENT ;
    PORT
      LAYER M4 ;
      RECT 51.656 86.592 51.680 86.616 ;
    END
  END addr_in_B[2]
  PIN addr_in_A[3]
    DIRECTION INPUT ;
    USE SIGNAL ;
    SHAPE ABUTMENT ;
    PORT
      LAYER M4 ;
      RECT 0.000 87.024 0.024 87.048 ;
    END
  END addr_in_A[3]
  PIN addr_in_B[3]
    DIRECTION INPUT ;
    USE SIGNAL ;
    SHAPE ABUTMENT ;
    PORT
      LAYER M4 ;
      RECT 51.656 87.024 51.680 87.048 ;
    END
  END addr_in_B[3]
  PIN addr_in_A[4]
    DIRECTION INPUT ;
    USE SIGNAL ;
    SHAPE ABUTMENT ;
    PORT
      LAYER M4 ;
      RECT 0.000 87.456 0.024 87.480 ;
    END
  END addr_in_A[4]
  PIN addr_in_B[4]
    DIRECTION INPUT ;
    USE SIGNAL ;
    SHAPE ABUTMENT ;
    PORT
      LAYER M4 ;
      RECT 51.656 87.456 51.680 87.480 ;
    END
  END addr_in_B[4]
  PIN addr_in_A[5]
    DIRECTION INPUT ;
    USE SIGNAL ;
    SHAPE ABUTMENT ;
    PORT
      LAYER M4 ;
      RECT 0.000 87.888 0.024 87.912 ;
    END
  END addr_in_A[5]
  PIN addr_in_B[5]
    DIRECTION INPUT ;
    USE SIGNAL ;
    SHAPE ABUTMENT ;
    PORT
      LAYER M4 ;
      RECT 51.656 87.888 51.680 87.912 ;
    END
  END addr_in_B[5]
  PIN addr_in_A[6]
    DIRECTION INPUT ;
    USE SIGNAL ;
    SHAPE ABUTMENT ;
    PORT
      LAYER M4 ;
      RECT 0.000 88.320 0.024 88.344 ;
    END
  END addr_in_A[6]
  PIN addr_in_B[6]
    DIRECTION INPUT ;
    USE SIGNAL ;
    SHAPE ABUTMENT ;
    PORT
      LAYER M4 ;
      RECT 51.656 88.320 51.680 88.344 ;
    END
  END addr_in_B[6]
  PIN addr_in_A[7]
    DIRECTION INPUT ;
    USE SIGNAL ;
    SHAPE ABUTMENT ;
    PORT
      LAYER M4 ;
      RECT 0.000 88.752 0.024 88.776 ;
    END
  END addr_in_A[7]
  PIN addr_in_B[7]
    DIRECTION INPUT ;
    USE SIGNAL ;
    SHAPE ABUTMENT ;
    PORT
      LAYER M4 ;
      RECT 51.656 88.752 51.680 88.776 ;
    END
  END addr_in_B[7]
  PIN addr_in_A[8]
    DIRECTION INPUT ;
    USE SIGNAL ;
    SHAPE ABUTMENT ;
    PORT
      LAYER M4 ;
      RECT 0.000 89.184 0.024 89.208 ;
    END
  END addr_in_A[8]
  PIN addr_in_B[8]
    DIRECTION INPUT ;
    USE SIGNAL ;
    SHAPE ABUTMENT ;
    PORT
      LAYER M4 ;
      RECT 51.656 89.184 51.680 89.208 ;
    END
  END addr_in_B[8]
  PIN addr_in_A[9]
    DIRECTION INPUT ;
    USE SIGNAL ;
    SHAPE ABUTMENT ;
    PORT
      LAYER M4 ;
      RECT 0.000 89.616 0.024 89.640 ;
    END
  END addr_in_A[9]
  PIN addr_in_B[9]
    DIRECTION INPUT ;
    USE SIGNAL ;
    SHAPE ABUTMENT ;
    PORT
      LAYER M4 ;
      RECT 51.656 89.616 51.680 89.640 ;
    END
  END addr_in_B[9]
  PIN we_in_A
    DIRECTION INPUT ;
    USE SIGNAL ;
    SHAPE ABUTMENT ;
    PORT
      LAYER M4 ;
      RECT 0.000 90.960 0.024 90.984 ;
    END
  END we_in_A
  PIN we_in_B
    DIRECTION INPUT ;
    USE SIGNAL ;
    SHAPE ABUTMENT ;
    PORT
      LAYER M4 ;
      RECT 51.656 90.960 51.680 90.984 ;
    END
  END we_in_B
  PIN ce_in_A
    DIRECTION INPUT ;
    USE SIGNAL ;
    SHAPE ABUTMENT ;
    PORT
      LAYER M4 ;
      RECT 0.000 91.392 0.024 91.416 ;
    END
  END ce_in_A
  PIN clk_A
    DIRECTION INPUT ;
    USE SIGNAL ;
    SHAPE ABUTMENT ;
    PORT
      LAYER M4 ;
      RECT 0.000 91.824 0.024 91.848 ;
    END
  END clk_A
  PIN ce_in_B
    DIRECTION INPUT ;
    USE SIGNAL ;
    SHAPE ABUTMENT ;
    PORT
      LAYER M4 ;
      RECT 0.000 92.256 0.024 92.280 ;
    END
  END ce_in_B
  PIN clk_B
    DIRECTION INPUT ;
    USE SIGNAL ;
    SHAPE ABUTMENT ;
    PORT
      LAYER M4 ;
      RECT 0.000 92.688 0.024 92.712 ;
    END
  END clk_B
  PIN VSS
    DIRECTION INOUT ;
    USE GROUND ;
    PORT
      LAYER M4 ;
      RECT 0.048 0.000 51.632 0.096 ;
      RECT 0.048 0.768 51.632 0.864 ;
      RECT 0.048 1.536 51.632 1.632 ;
      RECT 0.048 2.304 51.632 2.400 ;
      RECT 0.048 3.072 51.632 3.168 ;
      RECT 0.048 3.840 51.632 3.936 ;
      RECT 0.048 4.608 51.632 4.704 ;
      RECT 0.048 5.376 51.632 5.472 ;
      RECT 0.048 6.144 51.632 6.240 ;
      RECT 0.048 6.912 51.632 7.008 ;
      RECT 0.048 7.680 51.632 7.776 ;
      RECT 0.048 8.448 51.632 8.544 ;
      RECT 0.048 9.216 51.632 9.312 ;
      RECT 0.048 9.984 51.632 10.080 ;
      RECT 0.048 10.752 51.632 10.848 ;
      RECT 0.048 11.520 51.632 11.616 ;
      RECT 0.048 12.288 51.632 12.384 ;
      RECT 0.048 13.056 51.632 13.152 ;
      RECT 0.048 13.824 51.632 13.920 ;
      RECT 0.048 14.592 51.632 14.688 ;
      RECT 0.048 15.360 51.632 15.456 ;
      RECT 0.048 16.128 51.632 16.224 ;
      RECT 0.048 16.896 51.632 16.992 ;
      RECT 0.048 17.664 51.632 17.760 ;
      RECT 0.048 18.432 51.632 18.528 ;
      RECT 0.048 19.200 51.632 19.296 ;
      RECT 0.048 19.968 51.632 20.064 ;
      RECT 0.048 20.736 51.632 20.832 ;
      RECT 0.048 21.504 51.632 21.600 ;
      RECT 0.048 22.272 51.632 22.368 ;
      RECT 0.048 23.040 51.632 23.136 ;
      RECT 0.048 23.808 51.632 23.904 ;
      RECT 0.048 24.576 51.632 24.672 ;
      RECT 0.048 25.344 51.632 25.440 ;
      RECT 0.048 26.112 51.632 26.208 ;
      RECT 0.048 26.880 51.632 26.976 ;
      RECT 0.048 27.648 51.632 27.744 ;
      RECT 0.048 28.416 51.632 28.512 ;
      RECT 0.048 29.184 51.632 29.280 ;
      RECT 0.048 29.952 51.632 30.048 ;
      RECT 0.048 30.720 51.632 30.816 ;
      RECT 0.048 31.488 51.632 31.584 ;
      RECT 0.048 32.256 51.632 32.352 ;
      RECT 0.048 33.024 51.632 33.120 ;
      RECT 0.048 33.792 51.632 33.888 ;
      RECT 0.048 34.560 51.632 34.656 ;
      RECT 0.048 35.328 51.632 35.424 ;
      RECT 0.048 36.096 51.632 36.192 ;
      RECT 0.048 36.864 51.632 36.960 ;
      RECT 0.048 37.632 51.632 37.728 ;
      RECT 0.048 38.400 51.632 38.496 ;
      RECT 0.048 39.168 51.632 39.264 ;
      RECT 0.048 39.936 51.632 40.032 ;
      RECT 0.048 40.704 51.632 40.800 ;
      RECT 0.048 41.472 51.632 41.568 ;
      RECT 0.048 42.240 51.632 42.336 ;
      RECT 0.048 43.008 51.632 43.104 ;
      RECT 0.048 43.776 51.632 43.872 ;
      RECT 0.048 44.544 51.632 44.640 ;
      RECT 0.048 45.312 51.632 45.408 ;
      RECT 0.048 46.080 51.632 46.176 ;
      RECT 0.048 46.848 51.632 46.944 ;
      RECT 0.048 47.616 51.632 47.712 ;
      RECT 0.048 48.384 51.632 48.480 ;
      RECT 0.048 49.152 51.632 49.248 ;
      RECT 0.048 49.920 51.632 50.016 ;
      RECT 0.048 50.688 51.632 50.784 ;
      RECT 0.048 51.456 51.632 51.552 ;
      RECT 0.048 52.224 51.632 52.320 ;
      RECT 0.048 52.992 51.632 53.088 ;
      RECT 0.048 53.760 51.632 53.856 ;
      RECT 0.048 54.528 51.632 54.624 ;
      RECT 0.048 55.296 51.632 55.392 ;
      RECT 0.048 56.064 51.632 56.160 ;
      RECT 0.048 56.832 51.632 56.928 ;
      RECT 0.048 57.600 51.632 57.696 ;
      RECT 0.048 58.368 51.632 58.464 ;
      RECT 0.048 59.136 51.632 59.232 ;
      RECT 0.048 59.904 51.632 60.000 ;
      RECT 0.048 60.672 51.632 60.768 ;
      RECT 0.048 61.440 51.632 61.536 ;
      RECT 0.048 62.208 51.632 62.304 ;
      RECT 0.048 62.976 51.632 63.072 ;
      RECT 0.048 63.744 51.632 63.840 ;
      RECT 0.048 64.512 51.632 64.608 ;
      RECT 0.048 65.280 51.632 65.376 ;
      RECT 0.048 66.048 51.632 66.144 ;
      RECT 0.048 66.816 51.632 66.912 ;
      RECT 0.048 67.584 51.632 67.680 ;
      RECT 0.048 68.352 51.632 68.448 ;
      RECT 0.048 69.120 51.632 69.216 ;
      RECT 0.048 69.888 51.632 69.984 ;
      RECT 0.048 70.656 51.632 70.752 ;
      RECT 0.048 71.424 51.632 71.520 ;
      RECT 0.048 72.192 51.632 72.288 ;
      RECT 0.048 72.960 51.632 73.056 ;
      RECT 0.048 73.728 51.632 73.824 ;
      RECT 0.048 74.496 51.632 74.592 ;
      RECT 0.048 75.264 51.632 75.360 ;
      RECT 0.048 76.032 51.632 76.128 ;
      RECT 0.048 76.800 51.632 76.896 ;
      RECT 0.048 77.568 51.632 77.664 ;
      RECT 0.048 78.336 51.632 78.432 ;
      RECT 0.048 79.104 51.632 79.200 ;
      RECT 0.048 79.872 51.632 79.968 ;
      RECT 0.048 80.640 51.632 80.736 ;
      RECT 0.048 81.408 51.632 81.504 ;
      RECT 0.048 82.176 51.632 82.272 ;
      RECT 0.048 82.944 51.632 83.040 ;
      RECT 0.048 83.712 51.632 83.808 ;
      RECT 0.048 84.480 51.632 84.576 ;
      RECT 0.048 85.248 51.632 85.344 ;
      RECT 0.048 86.016 51.632 86.112 ;
      RECT 0.048 86.784 51.632 86.880 ;
      RECT 0.048 87.552 51.632 87.648 ;
      RECT 0.048 88.320 51.632 88.416 ;
      RECT 0.048 89.088 51.632 89.184 ;
      RECT 0.048 89.856 51.632 89.952 ;
      RECT 0.048 90.624 51.632 90.720 ;
      RECT 0.048 91.392 51.632 91.488 ;
      RECT 0.048 92.160 51.632 92.256 ;
    END
  END VSS
  PIN VDD
    DIRECTION INOUT ;
    USE POWER ;
    PORT
      LAYER M4 ;
      RECT 0.048 0.384 51.632 0.480 ;
      RECT 0.048 1.152 51.632 1.248 ;
      RECT 0.048 1.920 51.632 2.016 ;
      RECT 0.048 2.688 51.632 2.784 ;
      RECT 0.048 3.456 51.632 3.552 ;
      RECT 0.048 4.224 51.632 4.320 ;
      RECT 0.048 4.992 51.632 5.088 ;
      RECT 0.048 5.760 51.632 5.856 ;
      RECT 0.048 6.528 51.632 6.624 ;
      RECT 0.048 7.296 51.632 7.392 ;
      RECT 0.048 8.064 51.632 8.160 ;
      RECT 0.048 8.832 51.632 8.928 ;
      RECT 0.048 9.600 51.632 9.696 ;
      RECT 0.048 10.368 51.632 10.464 ;
      RECT 0.048 11.136 51.632 11.232 ;
      RECT 0.048 11.904 51.632 12.000 ;
      RECT 0.048 12.672 51.632 12.768 ;
      RECT 0.048 13.440 51.632 13.536 ;
      RECT 0.048 14.208 51.632 14.304 ;
      RECT 0.048 14.976 51.632 15.072 ;
      RECT 0.048 15.744 51.632 15.840 ;
      RECT 0.048 16.512 51.632 16.608 ;
      RECT 0.048 17.280 51.632 17.376 ;
      RECT 0.048 18.048 51.632 18.144 ;
      RECT 0.048 18.816 51.632 18.912 ;
      RECT 0.048 19.584 51.632 19.680 ;
      RECT 0.048 20.352 51.632 20.448 ;
      RECT 0.048 21.120 51.632 21.216 ;
      RECT 0.048 21.888 51.632 21.984 ;
      RECT 0.048 22.656 51.632 22.752 ;
      RECT 0.048 23.424 51.632 23.520 ;
      RECT 0.048 24.192 51.632 24.288 ;
      RECT 0.048 24.960 51.632 25.056 ;
      RECT 0.048 25.728 51.632 25.824 ;
      RECT 0.048 26.496 51.632 26.592 ;
      RECT 0.048 27.264 51.632 27.360 ;
      RECT 0.048 28.032 51.632 28.128 ;
      RECT 0.048 28.800 51.632 28.896 ;
      RECT 0.048 29.568 51.632 29.664 ;
      RECT 0.048 30.336 51.632 30.432 ;
      RECT 0.048 31.104 51.632 31.200 ;
      RECT 0.048 31.872 51.632 31.968 ;
      RECT 0.048 32.640 51.632 32.736 ;
      RECT 0.048 33.408 51.632 33.504 ;
      RECT 0.048 34.176 51.632 34.272 ;
      RECT 0.048 34.944 51.632 35.040 ;
      RECT 0.048 35.712 51.632 35.808 ;
      RECT 0.048 36.480 51.632 36.576 ;
      RECT 0.048 37.248 51.632 37.344 ;
      RECT 0.048 38.016 51.632 38.112 ;
      RECT 0.048 38.784 51.632 38.880 ;
      RECT 0.048 39.552 51.632 39.648 ;
      RECT 0.048 40.320 51.632 40.416 ;
      RECT 0.048 41.088 51.632 41.184 ;
      RECT 0.048 41.856 51.632 41.952 ;
      RECT 0.048 42.624 51.632 42.720 ;
      RECT 0.048 43.392 51.632 43.488 ;
      RECT 0.048 44.160 51.632 44.256 ;
      RECT 0.048 44.928 51.632 45.024 ;
      RECT 0.048 45.696 51.632 45.792 ;
      RECT 0.048 46.464 51.632 46.560 ;
      RECT 0.048 47.232 51.632 47.328 ;
      RECT 0.048 48.000 51.632 48.096 ;
      RECT 0.048 48.768 51.632 48.864 ;
      RECT 0.048 49.536 51.632 49.632 ;
      RECT 0.048 50.304 51.632 50.400 ;
      RECT 0.048 51.072 51.632 51.168 ;
      RECT 0.048 51.840 51.632 51.936 ;
      RECT 0.048 52.608 51.632 52.704 ;
      RECT 0.048 53.376 51.632 53.472 ;
      RECT 0.048 54.144 51.632 54.240 ;
      RECT 0.048 54.912 51.632 55.008 ;
      RECT 0.048 55.680 51.632 55.776 ;
      RECT 0.048 56.448 51.632 56.544 ;
      RECT 0.048 57.216 51.632 57.312 ;
      RECT 0.048 57.984 51.632 58.080 ;
      RECT 0.048 58.752 51.632 58.848 ;
      RECT 0.048 59.520 51.632 59.616 ;
      RECT 0.048 60.288 51.632 60.384 ;
      RECT 0.048 61.056 51.632 61.152 ;
      RECT 0.048 61.824 51.632 61.920 ;
      RECT 0.048 62.592 51.632 62.688 ;
      RECT 0.048 63.360 51.632 63.456 ;
      RECT 0.048 64.128 51.632 64.224 ;
      RECT 0.048 64.896 51.632 64.992 ;
      RECT 0.048 65.664 51.632 65.760 ;
      RECT 0.048 66.432 51.632 66.528 ;
      RECT 0.048 67.200 51.632 67.296 ;
      RECT 0.048 67.968 51.632 68.064 ;
      RECT 0.048 68.736 51.632 68.832 ;
      RECT 0.048 69.504 51.632 69.600 ;
      RECT 0.048 70.272 51.632 70.368 ;
      RECT 0.048 71.040 51.632 71.136 ;
      RECT 0.048 71.808 51.632 71.904 ;
      RECT 0.048 72.576 51.632 72.672 ;
      RECT 0.048 73.344 51.632 73.440 ;
      RECT 0.048 74.112 51.632 74.208 ;
      RECT 0.048 74.880 51.632 74.976 ;
      RECT 0.048 75.648 51.632 75.744 ;
      RECT 0.048 76.416 51.632 76.512 ;
      RECT 0.048 77.184 51.632 77.280 ;
      RECT 0.048 77.952 51.632 78.048 ;
      RECT 0.048 78.720 51.632 78.816 ;
      RECT 0.048 79.488 51.632 79.584 ;
      RECT 0.048 80.256 51.632 80.352 ;
      RECT 0.048 81.024 51.632 81.120 ;
      RECT 0.048 81.792 51.632 81.888 ;
      RECT 0.048 82.560 51.632 82.656 ;
      RECT 0.048 83.328 51.632 83.424 ;
      RECT 0.048 84.096 51.632 84.192 ;
      RECT 0.048 84.864 51.632 84.960 ;
      RECT 0.048 85.632 51.632 85.728 ;
      RECT 0.048 86.400 51.632 86.496 ;
      RECT 0.048 87.168 51.632 87.264 ;
      RECT 0.048 87.936 51.632 88.032 ;
      RECT 0.048 88.704 51.632 88.800 ;
      RECT 0.048 89.472 51.632 89.568 ;
      RECT 0.048 90.240 51.632 90.336 ;
      RECT 0.048 91.008 51.632 91.104 ;
      RECT 0.048 91.776 51.632 91.872 ;
    END
  END VDD
  OBS
    LAYER M1 ;
    RECT 0 0 51.680 92.400 ;
    LAYER M2 ;
    RECT 0 0 51.680 92.400 ;
    LAYER M3 ;
    RECT 0 0 51.680 92.400 ;
    LAYER M4 ;
    RECT 0 0 51.680 92.400 ;
  END
END fakeram7_tdp_1024x64

END LIBRARY
